# OpenTallas memory compiler (tools/mem_compiler), ASAP7 abstract view
VERSION 5.7 ;
BUSBITCHARS "[]" ;
DIVIDERCHAR "/" ;
PROPERTYDEFINITIONS
  MACRO width INTEGER ;
  MACRO depth INTEGER ;
  MACRO banks INTEGER ;
END PROPERTYDEFINITIONS
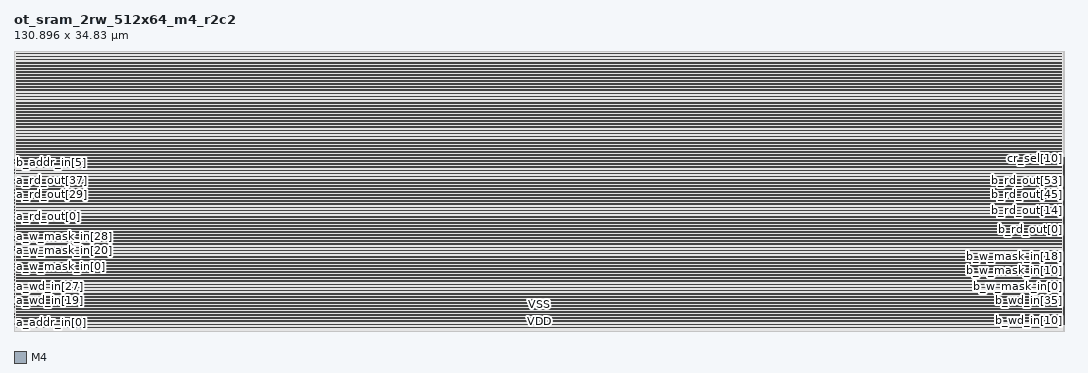
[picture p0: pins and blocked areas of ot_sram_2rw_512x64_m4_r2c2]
MACRO ot_sram_2rw_512x64_m4_r2c2
  PROPERTY width 64 ;
  PROPERTY depth 512 ;
  PROPERTY banks 1 ;
  FOREIGN ot_sram_2rw_512x64_m4_r2c2 0 0 ;
  SYMMETRY X Y R90 ;
  SIZE 130.896 BY 34.830 ;
  CLASS BLOCK ;
  PIN clk
    DIRECTION INPUT ;
    USE CLOCK ;
    SHAPE ABUTMENT ;
    PORT
      LAYER M4 ;
      RECT 0.000 0.768 0.024 0.792 ;
    END
  END clk
  PIN a_ce_in
    DIRECTION INPUT ;
    USE SIGNAL ;
    SHAPE ABUTMENT ;
    PORT
      LAYER M4 ;
      RECT 0.000 0.864 0.024 0.888 ;
    END
  END a_ce_in
  PIN a_we_in
    DIRECTION INPUT ;
    USE SIGNAL ;
    SHAPE ABUTMENT ;
    PORT
      LAYER M4 ;
      RECT 0.000 0.960 0.024 0.984 ;
    END
  END a_we_in
  PIN a_addr_in[0]
    DIRECTION INPUT ;
    USE SIGNAL ;
    SHAPE ABUTMENT ;
    PORT
      LAYER M4 ;
      RECT 0.000 1.056 0.024 1.080 ;
    END
  END a_addr_in[0]
  PIN a_addr_in[1]
    DIRECTION INPUT ;
    USE SIGNAL ;
    SHAPE ABUTMENT ;
    PORT
      LAYER M4 ;
      RECT 0.000 1.152 0.024 1.176 ;
    END
  END a_addr_in[1]
  PIN a_addr_in[2]
    DIRECTION INPUT ;
    USE SIGNAL ;
    SHAPE ABUTMENT ;
    PORT
      LAYER M4 ;
      RECT 0.000 1.248 0.024 1.272 ;
    END
  END a_addr_in[2]
  PIN a_addr_in[3]
    DIRECTION INPUT ;
    USE SIGNAL ;
    SHAPE ABUTMENT ;
    PORT
      LAYER M4 ;
      RECT 0.000 1.344 0.024 1.368 ;
    END
  END a_addr_in[3]
  PIN a_addr_in[4]
    DIRECTION INPUT ;
    USE SIGNAL ;
    SHAPE ABUTMENT ;
    PORT
      LAYER M4 ;
      RECT 0.000 1.440 0.024 1.464 ;
    END
  END a_addr_in[4]
  PIN a_addr_in[5]
    DIRECTION INPUT ;
    USE SIGNAL ;
    SHAPE ABUTMENT ;
    PORT
      LAYER M4 ;
      RECT 0.000 1.536 0.024 1.560 ;
    END
  END a_addr_in[5]
  PIN a_addr_in[6]
    DIRECTION INPUT ;
    USE SIGNAL ;
    SHAPE ABUTMENT ;
    PORT
      LAYER M4 ;
      RECT 0.000 1.632 0.024 1.656 ;
    END
  END a_addr_in[6]
  PIN a_addr_in[7]
    DIRECTION INPUT ;
    USE SIGNAL ;
    SHAPE ABUTMENT ;
    PORT
      LAYER M4 ;
      RECT 0.000 1.728 0.024 1.752 ;
    END
  END a_addr_in[7]
  PIN a_addr_in[8]
    DIRECTION INPUT ;
    USE SIGNAL ;
    SHAPE ABUTMENT ;
    PORT
      LAYER M4 ;
      RECT 0.000 1.824 0.024 1.848 ;
    END
  END a_addr_in[8]
  PIN a_wd_in[0]
    DIRECTION INPUT ;
    USE SIGNAL ;
    SHAPE ABUTMENT ;
    PORT
      LAYER M4 ;
      RECT 0.000 1.920 0.024 1.944 ;
    END
  END a_wd_in[0]
  PIN a_wd_in[1]
    DIRECTION INPUT ;
    USE SIGNAL ;
    SHAPE ABUTMENT ;
    PORT
      LAYER M4 ;
      RECT 0.000 2.016 0.024 2.040 ;
    END
  END a_wd_in[1]
  PIN a_wd_in[2]
    DIRECTION INPUT ;
    USE SIGNAL ;
    SHAPE ABUTMENT ;
    PORT
      LAYER M4 ;
      RECT 0.000 2.112 0.024 2.136 ;
    END
  END a_wd_in[2]
  PIN a_wd_in[3]
    DIRECTION INPUT ;
    USE SIGNAL ;
    SHAPE ABUTMENT ;
    PORT
      LAYER M4 ;
      RECT 0.000 2.208 0.024 2.232 ;
    END
  END a_wd_in[3]
  PIN a_wd_in[4]
    DIRECTION INPUT ;
    USE SIGNAL ;
    SHAPE ABUTMENT ;
    PORT
      LAYER M4 ;
      RECT 0.000 2.304 0.024 2.328 ;
    END
  END a_wd_in[4]
  PIN a_wd_in[5]
    DIRECTION INPUT ;
    USE SIGNAL ;
    SHAPE ABUTMENT ;
    PORT
      LAYER M4 ;
      RECT 0.000 2.400 0.024 2.424 ;
    END
  END a_wd_in[5]
  PIN a_wd_in[6]
    DIRECTION INPUT ;
    USE SIGNAL ;
    SHAPE ABUTMENT ;
    PORT
      LAYER M4 ;
      RECT 0.000 2.496 0.024 2.520 ;
    END
  END a_wd_in[6]
  PIN a_wd_in[7]
    DIRECTION INPUT ;
    USE SIGNAL ;
    SHAPE ABUTMENT ;
    PORT
      LAYER M4 ;
      RECT 0.000 2.592 0.024 2.616 ;
    END
  END a_wd_in[7]
  PIN a_wd_in[8]
    DIRECTION INPUT ;
    USE SIGNAL ;
    SHAPE ABUTMENT ;
    PORT
      LAYER M4 ;
      RECT 0.000 2.688 0.024 2.712 ;
    END
  END a_wd_in[8]
  PIN a_wd_in[9]
    DIRECTION INPUT ;
    USE SIGNAL ;
    SHAPE ABUTMENT ;
    PORT
      LAYER M4 ;
      RECT 0.000 2.784 0.024 2.808 ;
    END
  END a_wd_in[9]
  PIN a_wd_in[10]
    DIRECTION INPUT ;
    USE SIGNAL ;
    SHAPE ABUTMENT ;
    PORT
      LAYER M4 ;
      RECT 0.000 2.880 0.024 2.904 ;
    END
  END a_wd_in[10]
  PIN a_wd_in[11]
    DIRECTION INPUT ;
    USE SIGNAL ;
    SHAPE ABUTMENT ;
    PORT
      LAYER M4 ;
      RECT 0.000 2.976 0.024 3.000 ;
    END
  END a_wd_in[11]
  PIN a_wd_in[12]
    DIRECTION INPUT ;
    USE SIGNAL ;
    SHAPE ABUTMENT ;
    PORT
      LAYER M4 ;
      RECT 0.000 3.072 0.024 3.096 ;
    END
  END a_wd_in[12]
  PIN a_wd_in[13]
    DIRECTION INPUT ;
    USE SIGNAL ;
    SHAPE ABUTMENT ;
    PORT
      LAYER M4 ;
      RECT 0.000 3.168 0.024 3.192 ;
    END
  END a_wd_in[13]
  PIN a_wd_in[14]
    DIRECTION INPUT ;
    USE SIGNAL ;
    SHAPE ABUTMENT ;
    PORT
      LAYER M4 ;
      RECT 0.000 3.264 0.024 3.288 ;
    END
  END a_wd_in[14]
  PIN a_wd_in[15]
    DIRECTION INPUT ;
    USE SIGNAL ;
    SHAPE ABUTMENT ;
    PORT
      LAYER M4 ;
      RECT 0.000 3.360 0.024 3.384 ;
    END
  END a_wd_in[15]
  PIN a_wd_in[16]
    DIRECTION INPUT ;
    USE SIGNAL ;
    SHAPE ABUTMENT ;
    PORT
      LAYER M4 ;
      RECT 0.000 3.456 0.024 3.480 ;
    END
  END a_wd_in[16]
  PIN a_wd_in[17]
    DIRECTION INPUT ;
    USE SIGNAL ;
    SHAPE ABUTMENT ;
    PORT
      LAYER M4 ;
      RECT 0.000 3.552 0.024 3.576 ;
    END
  END a_wd_in[17]
  PIN a_wd_in[18]
    DIRECTION INPUT ;
    USE SIGNAL ;
    SHAPE ABUTMENT ;
    PORT
      LAYER M4 ;
      RECT 0.000 3.648 0.024 3.672 ;
    END
  END a_wd_in[18]
  PIN a_wd_in[19]
    DIRECTION INPUT ;
    USE SIGNAL ;
    SHAPE ABUTMENT ;
    PORT
      LAYER M4 ;
      RECT 0.000 3.744 0.024 3.768 ;
    END
  END a_wd_in[19]
  PIN a_wd_in[20]
    DIRECTION INPUT ;
    USE SIGNAL ;
    SHAPE ABUTMENT ;
    PORT
      LAYER M4 ;
      RECT 0.000 3.840 0.024 3.864 ;
    END
  END a_wd_in[20]
  PIN a_wd_in[21]
    DIRECTION INPUT ;
    USE SIGNAL ;
    SHAPE ABUTMENT ;
    PORT
      LAYER M4 ;
      RECT 0.000 3.936 0.024 3.960 ;
    END
  END a_wd_in[21]
  PIN a_wd_in[22]
    DIRECTION INPUT ;
    USE SIGNAL ;
    SHAPE ABUTMENT ;
    PORT
      LAYER M4 ;
      RECT 0.000 4.032 0.024 4.056 ;
    END
  END a_wd_in[22]
  PIN a_wd_in[23]
    DIRECTION INPUT ;
    USE SIGNAL ;
    SHAPE ABUTMENT ;
    PORT
      LAYER M4 ;
      RECT 0.000 4.128 0.024 4.152 ;
    END
  END a_wd_in[23]
  PIN a_wd_in[24]
    DIRECTION INPUT ;
    USE SIGNAL ;
    SHAPE ABUTMENT ;
    PORT
      LAYER M4 ;
      RECT 0.000 4.224 0.024 4.248 ;
    END
  END a_wd_in[24]
  PIN a_wd_in[25]
    DIRECTION INPUT ;
    USE SIGNAL ;
    SHAPE ABUTMENT ;
    PORT
      LAYER M4 ;
      RECT 0.000 4.320 0.024 4.344 ;
    END
  END a_wd_in[25]
  PIN a_wd_in[26]
    DIRECTION INPUT ;
    USE SIGNAL ;
    SHAPE ABUTMENT ;
    PORT
      LAYER M4 ;
      RECT 0.000 4.416 0.024 4.440 ;
    END
  END a_wd_in[26]
  PIN a_wd_in[27]
    DIRECTION INPUT ;
    USE SIGNAL ;
    SHAPE ABUTMENT ;
    PORT
      LAYER M4 ;
      RECT 0.000 4.512 0.024 4.536 ;
    END
  END a_wd_in[27]
  PIN a_wd_in[28]
    DIRECTION INPUT ;
    USE SIGNAL ;
    SHAPE ABUTMENT ;
    PORT
      LAYER M4 ;
      RECT 0.000 4.608 0.024 4.632 ;
    END
  END a_wd_in[28]
  PIN a_wd_in[29]
    DIRECTION INPUT ;
    USE SIGNAL ;
    SHAPE ABUTMENT ;
    PORT
      LAYER M4 ;
      RECT 0.000 4.704 0.024 4.728 ;
    END
  END a_wd_in[29]
  PIN a_wd_in[30]
    DIRECTION INPUT ;
    USE SIGNAL ;
    SHAPE ABUTMENT ;
    PORT
      LAYER M4 ;
      RECT 0.000 4.800 0.024 4.824 ;
    END
  END a_wd_in[30]
  PIN a_wd_in[31]
    DIRECTION INPUT ;
    USE SIGNAL ;
    SHAPE ABUTMENT ;
    PORT
      LAYER M4 ;
      RECT 0.000 4.896 0.024 4.920 ;
    END
  END a_wd_in[31]
  PIN a_wd_in[32]
    DIRECTION INPUT ;
    USE SIGNAL ;
    SHAPE ABUTMENT ;
    PORT
      LAYER M4 ;
      RECT 0.000 4.992 0.024 5.016 ;
    END
  END a_wd_in[32]
  PIN a_wd_in[33]
    DIRECTION INPUT ;
    USE SIGNAL ;
    SHAPE ABUTMENT ;
    PORT
      LAYER M4 ;
      RECT 0.000 5.088 0.024 5.112 ;
    END
  END a_wd_in[33]
  PIN a_wd_in[34]
    DIRECTION INPUT ;
    USE SIGNAL ;
    SHAPE ABUTMENT ;
    PORT
      LAYER M4 ;
      RECT 0.000 5.184 0.024 5.208 ;
    END
  END a_wd_in[34]
  PIN a_wd_in[35]
    DIRECTION INPUT ;
    USE SIGNAL ;
    SHAPE ABUTMENT ;
    PORT
      LAYER M4 ;
      RECT 0.000 5.280 0.024 5.304 ;
    END
  END a_wd_in[35]
  PIN a_wd_in[36]
    DIRECTION INPUT ;
    USE SIGNAL ;
    SHAPE ABUTMENT ;
    PORT
      LAYER M4 ;
      RECT 0.000 5.376 0.024 5.400 ;
    END
  END a_wd_in[36]
  PIN a_wd_in[37]
    DIRECTION INPUT ;
    USE SIGNAL ;
    SHAPE ABUTMENT ;
    PORT
      LAYER M4 ;
      RECT 0.000 5.472 0.024 5.496 ;
    END
  END a_wd_in[37]
  PIN a_wd_in[38]
    DIRECTION INPUT ;
    USE SIGNAL ;
    SHAPE ABUTMENT ;
    PORT
      LAYER M4 ;
      RECT 0.000 5.568 0.024 5.592 ;
    END
  END a_wd_in[38]
  PIN a_wd_in[39]
    DIRECTION INPUT ;
    USE SIGNAL ;
    SHAPE ABUTMENT ;
    PORT
      LAYER M4 ;
      RECT 0.000 5.664 0.024 5.688 ;
    END
  END a_wd_in[39]
  PIN a_wd_in[40]
    DIRECTION INPUT ;
    USE SIGNAL ;
    SHAPE ABUTMENT ;
    PORT
      LAYER M4 ;
      RECT 0.000 5.760 0.024 5.784 ;
    END
  END a_wd_in[40]
  PIN a_wd_in[41]
    DIRECTION INPUT ;
    USE SIGNAL ;
    SHAPE ABUTMENT ;
    PORT
      LAYER M4 ;
      RECT 0.000 5.856 0.024 5.880 ;
    END
  END a_wd_in[41]
  PIN a_wd_in[42]
    DIRECTION INPUT ;
    USE SIGNAL ;
    SHAPE ABUTMENT ;
    PORT
      LAYER M4 ;
      RECT 0.000 5.952 0.024 5.976 ;
    END
  END a_wd_in[42]
  PIN a_wd_in[43]
    DIRECTION INPUT ;
    USE SIGNAL ;
    SHAPE ABUTMENT ;
    PORT
      LAYER M4 ;
      RECT 0.000 6.048 0.024 6.072 ;
    END
  END a_wd_in[43]
  PIN a_wd_in[44]
    DIRECTION INPUT ;
    USE SIGNAL ;
    SHAPE ABUTMENT ;
    PORT
      LAYER M4 ;
      RECT 0.000 6.144 0.024 6.168 ;
    END
  END a_wd_in[44]
  PIN a_wd_in[45]
    DIRECTION INPUT ;
    USE SIGNAL ;
    SHAPE ABUTMENT ;
    PORT
      LAYER M4 ;
      RECT 0.000 6.240 0.024 6.264 ;
    END
  END a_wd_in[45]
  PIN a_wd_in[46]
    DIRECTION INPUT ;
    USE SIGNAL ;
    SHAPE ABUTMENT ;
    PORT
      LAYER M4 ;
      RECT 0.000 6.336 0.024 6.360 ;
    END
  END a_wd_in[46]
  PIN a_wd_in[47]
    DIRECTION INPUT ;
    USE SIGNAL ;
    SHAPE ABUTMENT ;
    PORT
      LAYER M4 ;
      RECT 0.000 6.432 0.024 6.456 ;
    END
  END a_wd_in[47]
  PIN a_wd_in[48]
    DIRECTION INPUT ;
    USE SIGNAL ;
    SHAPE ABUTMENT ;
    PORT
      LAYER M4 ;
      RECT 0.000 6.528 0.024 6.552 ;
    END
  END a_wd_in[48]
  PIN a_wd_in[49]
    DIRECTION INPUT ;
    USE SIGNAL ;
    SHAPE ABUTMENT ;
    PORT
      LAYER M4 ;
      RECT 0.000 6.624 0.024 6.648 ;
    END
  END a_wd_in[49]
  PIN a_wd_in[50]
    DIRECTION INPUT ;
    USE SIGNAL ;
    SHAPE ABUTMENT ;
    PORT
      LAYER M4 ;
      RECT 0.000 6.720 0.024 6.744 ;
    END
  END a_wd_in[50]
  PIN a_wd_in[51]
    DIRECTION INPUT ;
    USE SIGNAL ;
    SHAPE ABUTMENT ;
    PORT
      LAYER M4 ;
      RECT 0.000 6.816 0.024 6.840 ;
    END
  END a_wd_in[51]
  PIN a_wd_in[52]
    DIRECTION INPUT ;
    USE SIGNAL ;
    SHAPE ABUTMENT ;
    PORT
      LAYER M4 ;
      RECT 0.000 6.912 0.024 6.936 ;
    END
  END a_wd_in[52]
  PIN a_wd_in[53]
    DIRECTION INPUT ;
    USE SIGNAL ;
    SHAPE ABUTMENT ;
    PORT
      LAYER M4 ;
      RECT 0.000 7.008 0.024 7.032 ;
    END
  END a_wd_in[53]
  PIN a_wd_in[54]
    DIRECTION INPUT ;
    USE SIGNAL ;
    SHAPE ABUTMENT ;
    PORT
      LAYER M4 ;
      RECT 0.000 7.104 0.024 7.128 ;
    END
  END a_wd_in[54]
  PIN a_wd_in[55]
    DIRECTION INPUT ;
    USE SIGNAL ;
    SHAPE ABUTMENT ;
    PORT
      LAYER M4 ;
      RECT 0.000 7.200 0.024 7.224 ;
    END
  END a_wd_in[55]
  PIN a_wd_in[56]
    DIRECTION INPUT ;
    USE SIGNAL ;
    SHAPE ABUTMENT ;
    PORT
      LAYER M4 ;
      RECT 0.000 7.296 0.024 7.320 ;
    END
  END a_wd_in[56]
  PIN a_wd_in[57]
    DIRECTION INPUT ;
    USE SIGNAL ;
    SHAPE ABUTMENT ;
    PORT
      LAYER M4 ;
      RECT 0.000 7.392 0.024 7.416 ;
    END
  END a_wd_in[57]
  PIN a_wd_in[58]
    DIRECTION INPUT ;
    USE SIGNAL ;
    SHAPE ABUTMENT ;
    PORT
      LAYER M4 ;
      RECT 0.000 7.488 0.024 7.512 ;
    END
  END a_wd_in[58]
  PIN a_wd_in[59]
    DIRECTION INPUT ;
    USE SIGNAL ;
    SHAPE ABUTMENT ;
    PORT
      LAYER M4 ;
      RECT 0.000 7.584 0.024 7.608 ;
    END
  END a_wd_in[59]
  PIN a_wd_in[60]
    DIRECTION INPUT ;
    USE SIGNAL ;
    SHAPE ABUTMENT ;
    PORT
      LAYER M4 ;
      RECT 0.000 7.680 0.024 7.704 ;
    END
  END a_wd_in[60]
  PIN a_wd_in[61]
    DIRECTION INPUT ;
    USE SIGNAL ;
    SHAPE ABUTMENT ;
    PORT
      LAYER M4 ;
      RECT 0.000 7.776 0.024 7.800 ;
    END
  END a_wd_in[61]
  PIN a_wd_in[62]
    DIRECTION INPUT ;
    USE SIGNAL ;
    SHAPE ABUTMENT ;
    PORT
      LAYER M4 ;
      RECT 0.000 7.872 0.024 7.896 ;
    END
  END a_wd_in[62]
  PIN a_wd_in[63]
    DIRECTION INPUT ;
    USE SIGNAL ;
    SHAPE ABUTMENT ;
    PORT
      LAYER M4 ;
      RECT 0.000 7.968 0.024 7.992 ;
    END
  END a_wd_in[63]
  PIN a_w_mask_in[0]
    DIRECTION INPUT ;
    USE SIGNAL ;
    SHAPE ABUTMENT ;
    PORT
      LAYER M4 ;
      RECT 0.000 8.064 0.024 8.088 ;
    END
  END a_w_mask_in[0]
  PIN a_w_mask_in[1]
    DIRECTION INPUT ;
    USE SIGNAL ;
    SHAPE ABUTMENT ;
    PORT
      LAYER M4 ;
      RECT 0.000 8.160 0.024 8.184 ;
    END
  END a_w_mask_in[1]
  PIN a_w_mask_in[2]
    DIRECTION INPUT ;
    USE SIGNAL ;
    SHAPE ABUTMENT ;
    PORT
      LAYER M4 ;
      RECT 0.000 8.256 0.024 8.280 ;
    END
  END a_w_mask_in[2]
  PIN a_w_mask_in[3]
    DIRECTION INPUT ;
    USE SIGNAL ;
    SHAPE ABUTMENT ;
    PORT
      LAYER M4 ;
      RECT 0.000 8.352 0.024 8.376 ;
    END
  END a_w_mask_in[3]
  PIN a_w_mask_in[4]
    DIRECTION INPUT ;
    USE SIGNAL ;
    SHAPE ABUTMENT ;
    PORT
      LAYER M4 ;
      RECT 0.000 8.448 0.024 8.472 ;
    END
  END a_w_mask_in[4]
  PIN a_w_mask_in[5]
    DIRECTION INPUT ;
    USE SIGNAL ;
    SHAPE ABUTMENT ;
    PORT
      LAYER M4 ;
      RECT 0.000 8.544 0.024 8.568 ;
    END
  END a_w_mask_in[5]
  PIN a_w_mask_in[6]
    DIRECTION INPUT ;
    USE SIGNAL ;
    SHAPE ABUTMENT ;
    PORT
      LAYER M4 ;
      RECT 0.000 8.640 0.024 8.664 ;
    END
  END a_w_mask_in[6]
  PIN a_w_mask_in[7]
    DIRECTION INPUT ;
    USE SIGNAL ;
    SHAPE ABUTMENT ;
    PORT
      LAYER M4 ;
      RECT 0.000 8.736 0.024 8.760 ;
    END
  END a_w_mask_in[7]
  PIN a_w_mask_in[8]
    DIRECTION INPUT ;
    USE SIGNAL ;
    SHAPE ABUTMENT ;
    PORT
      LAYER M4 ;
      RECT 0.000 8.832 0.024 8.856 ;
    END
  END a_w_mask_in[8]
  PIN a_w_mask_in[9]
    DIRECTION INPUT ;
    USE SIGNAL ;
    SHAPE ABUTMENT ;
    PORT
      LAYER M4 ;
      RECT 0.000 8.928 0.024 8.952 ;
    END
  END a_w_mask_in[9]
  PIN a_w_mask_in[10]
    DIRECTION INPUT ;
    USE SIGNAL ;
    SHAPE ABUTMENT ;
    PORT
      LAYER M4 ;
      RECT 0.000 9.024 0.024 9.048 ;
    END
  END a_w_mask_in[10]
  PIN a_w_mask_in[11]
    DIRECTION INPUT ;
    USE SIGNAL ;
    SHAPE ABUTMENT ;
    PORT
      LAYER M4 ;
      RECT 0.000 9.120 0.024 9.144 ;
    END
  END a_w_mask_in[11]
  PIN a_w_mask_in[12]
    DIRECTION INPUT ;
    USE SIGNAL ;
    SHAPE ABUTMENT ;
    PORT
      LAYER M4 ;
      RECT 0.000 9.216 0.024 9.240 ;
    END
  END a_w_mask_in[12]
  PIN a_w_mask_in[13]
    DIRECTION INPUT ;
    USE SIGNAL ;
    SHAPE ABUTMENT ;
    PORT
      LAYER M4 ;
      RECT 0.000 9.312 0.024 9.336 ;
    END
  END a_w_mask_in[13]
  PIN a_w_mask_in[14]
    DIRECTION INPUT ;
    USE SIGNAL ;
    SHAPE ABUTMENT ;
    PORT
      LAYER M4 ;
      RECT 0.000 9.408 0.024 9.432 ;
    END
  END a_w_mask_in[14]
  PIN a_w_mask_in[15]
    DIRECTION INPUT ;
    USE SIGNAL ;
    SHAPE ABUTMENT ;
    PORT
      LAYER M4 ;
      RECT 0.000 9.504 0.024 9.528 ;
    END
  END a_w_mask_in[15]
  PIN a_w_mask_in[16]
    DIRECTION INPUT ;
    USE SIGNAL ;
    SHAPE ABUTMENT ;
    PORT
      LAYER M4 ;
      RECT 0.000 9.600 0.024 9.624 ;
    END
  END a_w_mask_in[16]
  PIN a_w_mask_in[17]
    DIRECTION INPUT ;
    USE SIGNAL ;
    SHAPE ABUTMENT ;
    PORT
      LAYER M4 ;
      RECT 0.000 9.696 0.024 9.720 ;
    END
  END a_w_mask_in[17]
  PIN a_w_mask_in[18]
    DIRECTION INPUT ;
    USE SIGNAL ;
    SHAPE ABUTMENT ;
    PORT
      LAYER M4 ;
      RECT 0.000 9.792 0.024 9.816 ;
    END
  END a_w_mask_in[18]
  PIN a_w_mask_in[19]
    DIRECTION INPUT ;
    USE SIGNAL ;
    SHAPE ABUTMENT ;
    PORT
      LAYER M4 ;
      RECT 0.000 9.888 0.024 9.912 ;
    END
  END a_w_mask_in[19]
  PIN a_w_mask_in[20]
    DIRECTION INPUT ;
    USE SIGNAL ;
    SHAPE ABUTMENT ;
    PORT
      LAYER M4 ;
      RECT 0.000 9.984 0.024 10.008 ;
    END
  END a_w_mask_in[20]
  PIN a_w_mask_in[21]
    DIRECTION INPUT ;
    USE SIGNAL ;
    SHAPE ABUTMENT ;
    PORT
      LAYER M4 ;
      RECT 0.000 10.080 0.024 10.104 ;
    END
  END a_w_mask_in[21]
  PIN a_w_mask_in[22]
    DIRECTION INPUT ;
    USE SIGNAL ;
    SHAPE ABUTMENT ;
    PORT
      LAYER M4 ;
      RECT 0.000 10.176 0.024 10.200 ;
    END
  END a_w_mask_in[22]
  PIN a_w_mask_in[23]
    DIRECTION INPUT ;
    USE SIGNAL ;
    SHAPE ABUTMENT ;
    PORT
      LAYER M4 ;
      RECT 0.000 10.272 0.024 10.296 ;
    END
  END a_w_mask_in[23]
  PIN a_w_mask_in[24]
    DIRECTION INPUT ;
    USE SIGNAL ;
    SHAPE ABUTMENT ;
    PORT
      LAYER M4 ;
      RECT 0.000 10.368 0.024 10.392 ;
    END
  END a_w_mask_in[24]
  PIN a_w_mask_in[25]
    DIRECTION INPUT ;
    USE SIGNAL ;
    SHAPE ABUTMENT ;
    PORT
      LAYER M4 ;
      RECT 0.000 10.464 0.024 10.488 ;
    END
  END a_w_mask_in[25]
  PIN a_w_mask_in[26]
    DIRECTION INPUT ;
    USE SIGNAL ;
    SHAPE ABUTMENT ;
    PORT
      LAYER M4 ;
      RECT 0.000 10.560 0.024 10.584 ;
    END
  END a_w_mask_in[26]
  PIN a_w_mask_in[27]
    DIRECTION INPUT ;
    USE SIGNAL ;
    SHAPE ABUTMENT ;
    PORT
      LAYER M4 ;
      RECT 0.000 10.656 0.024 10.680 ;
    END
  END a_w_mask_in[27]
  PIN a_w_mask_in[28]
    DIRECTION INPUT ;
    USE SIGNAL ;
    SHAPE ABUTMENT ;
    PORT
      LAYER M4 ;
      RECT 0.000 10.752 0.024 10.776 ;
    END
  END a_w_mask_in[28]
  PIN a_w_mask_in[29]
    DIRECTION INPUT ;
    USE SIGNAL ;
    SHAPE ABUTMENT ;
    PORT
      LAYER M4 ;
      RECT 0.000 10.848 0.024 10.872 ;
    END
  END a_w_mask_in[29]
  PIN a_w_mask_in[30]
    DIRECTION INPUT ;
    USE SIGNAL ;
    SHAPE ABUTMENT ;
    PORT
      LAYER M4 ;
      RECT 0.000 10.944 0.024 10.968 ;
    END
  END a_w_mask_in[30]
  PIN a_w_mask_in[31]
    DIRECTION INPUT ;
    USE SIGNAL ;
    SHAPE ABUTMENT ;
    PORT
      LAYER M4 ;
      RECT 0.000 11.040 0.024 11.064 ;
    END
  END a_w_mask_in[31]
  PIN a_w_mask_in[32]
    DIRECTION INPUT ;
    USE SIGNAL ;
    SHAPE ABUTMENT ;
    PORT
      LAYER M4 ;
      RECT 0.000 11.136 0.024 11.160 ;
    END
  END a_w_mask_in[32]
  PIN a_w_mask_in[33]
    DIRECTION INPUT ;
    USE SIGNAL ;
    SHAPE ABUTMENT ;
    PORT
      LAYER M4 ;
      RECT 0.000 11.232 0.024 11.256 ;
    END
  END a_w_mask_in[33]
  PIN a_w_mask_in[34]
    DIRECTION INPUT ;
    USE SIGNAL ;
    SHAPE ABUTMENT ;
    PORT
      LAYER M4 ;
      RECT 0.000 11.328 0.024 11.352 ;
    END
  END a_w_mask_in[34]
  PIN a_w_mask_in[35]
    DIRECTION INPUT ;
    USE SIGNAL ;
    SHAPE ABUTMENT ;
    PORT
      LAYER M4 ;
      RECT 0.000 11.424 0.024 11.448 ;
    END
  END a_w_mask_in[35]
  PIN a_w_mask_in[36]
    DIRECTION INPUT ;
    USE SIGNAL ;
    SHAPE ABUTMENT ;
    PORT
      LAYER M4 ;
      RECT 0.000 11.520 0.024 11.544 ;
    END
  END a_w_mask_in[36]
  PIN a_w_mask_in[37]
    DIRECTION INPUT ;
    USE SIGNAL ;
    SHAPE ABUTMENT ;
    PORT
      LAYER M4 ;
      RECT 0.000 11.616 0.024 11.640 ;
    END
  END a_w_mask_in[37]
  PIN a_w_mask_in[38]
    DIRECTION INPUT ;
    USE SIGNAL ;
    SHAPE ABUTMENT ;
    PORT
      LAYER M4 ;
      RECT 0.000 11.712 0.024 11.736 ;
    END
  END a_w_mask_in[38]
  PIN a_w_mask_in[39]
    DIRECTION INPUT ;
    USE SIGNAL ;
    SHAPE ABUTMENT ;
    PORT
      LAYER M4 ;
      RECT 0.000 11.808 0.024 11.832 ;
    END
  END a_w_mask_in[39]
  PIN a_w_mask_in[40]
    DIRECTION INPUT ;
    USE SIGNAL ;
    SHAPE ABUTMENT ;
    PORT
      LAYER M4 ;
      RECT 0.000 11.904 0.024 11.928 ;
    END
  END a_w_mask_in[40]
  PIN a_w_mask_in[41]
    DIRECTION INPUT ;
    USE SIGNAL ;
    SHAPE ABUTMENT ;
    PORT
      LAYER M4 ;
      RECT 0.000 12.000 0.024 12.024 ;
    END
  END a_w_mask_in[41]
  PIN a_w_mask_in[42]
    DIRECTION INPUT ;
    USE SIGNAL ;
    SHAPE ABUTMENT ;
    PORT
      LAYER M4 ;
      RECT 0.000 12.096 0.024 12.120 ;
    END
  END a_w_mask_in[42]
  PIN a_w_mask_in[43]
    DIRECTION INPUT ;
    USE SIGNAL ;
    SHAPE ABUTMENT ;
    PORT
      LAYER M4 ;
      RECT 0.000 12.192 0.024 12.216 ;
    END
  END a_w_mask_in[43]
  PIN a_w_mask_in[44]
    DIRECTION INPUT ;
    USE SIGNAL ;
    SHAPE ABUTMENT ;
    PORT
      LAYER M4 ;
      RECT 0.000 12.288 0.024 12.312 ;
    END
  END a_w_mask_in[44]
  PIN a_w_mask_in[45]
    DIRECTION INPUT ;
    USE SIGNAL ;
    SHAPE ABUTMENT ;
    PORT
      LAYER M4 ;
      RECT 0.000 12.384 0.024 12.408 ;
    END
  END a_w_mask_in[45]
  PIN a_w_mask_in[46]
    DIRECTION INPUT ;
    USE SIGNAL ;
    SHAPE ABUTMENT ;
    PORT
      LAYER M4 ;
      RECT 0.000 12.480 0.024 12.504 ;
    END
  END a_w_mask_in[46]
  PIN a_w_mask_in[47]
    DIRECTION INPUT ;
    USE SIGNAL ;
    SHAPE ABUTMENT ;
    PORT
      LAYER M4 ;
      RECT 0.000 12.576 0.024 12.600 ;
    END
  END a_w_mask_in[47]
  PIN a_w_mask_in[48]
    DIRECTION INPUT ;
    USE SIGNAL ;
    SHAPE ABUTMENT ;
    PORT
      LAYER M4 ;
      RECT 0.000 12.672 0.024 12.696 ;
    END
  END a_w_mask_in[48]
  PIN a_w_mask_in[49]
    DIRECTION INPUT ;
    USE SIGNAL ;
    SHAPE ABUTMENT ;
    PORT
      LAYER M4 ;
      RECT 0.000 12.768 0.024 12.792 ;
    END
  END a_w_mask_in[49]
  PIN a_w_mask_in[50]
    DIRECTION INPUT ;
    USE SIGNAL ;
    SHAPE ABUTMENT ;
    PORT
      LAYER M4 ;
      RECT 0.000 12.864 0.024 12.888 ;
    END
  END a_w_mask_in[50]
  PIN a_w_mask_in[51]
    DIRECTION INPUT ;
    USE SIGNAL ;
    SHAPE ABUTMENT ;
    PORT
      LAYER M4 ;
      RECT 0.000 12.960 0.024 12.984 ;
    END
  END a_w_mask_in[51]
  PIN a_w_mask_in[52]
    DIRECTION INPUT ;
    USE SIGNAL ;
    SHAPE ABUTMENT ;
    PORT
      LAYER M4 ;
      RECT 0.000 13.056 0.024 13.080 ;
    END
  END a_w_mask_in[52]
  PIN a_w_mask_in[53]
    DIRECTION INPUT ;
    USE SIGNAL ;
    SHAPE ABUTMENT ;
    PORT
      LAYER M4 ;
      RECT 0.000 13.152 0.024 13.176 ;
    END
  END a_w_mask_in[53]
  PIN a_w_mask_in[54]
    DIRECTION INPUT ;
    USE SIGNAL ;
    SHAPE ABUTMENT ;
    PORT
      LAYER M4 ;
      RECT 0.000 13.248 0.024 13.272 ;
    END
  END a_w_mask_in[54]
  PIN a_w_mask_in[55]
    DIRECTION INPUT ;
    USE SIGNAL ;
    SHAPE ABUTMENT ;
    PORT
      LAYER M4 ;
      RECT 0.000 13.344 0.024 13.368 ;
    END
  END a_w_mask_in[55]
  PIN a_w_mask_in[56]
    DIRECTION INPUT ;
    USE SIGNAL ;
    SHAPE ABUTMENT ;
    PORT
      LAYER M4 ;
      RECT 0.000 13.440 0.024 13.464 ;
    END
  END a_w_mask_in[56]
  PIN a_w_mask_in[57]
    DIRECTION INPUT ;
    USE SIGNAL ;
    SHAPE ABUTMENT ;
    PORT
      LAYER M4 ;
      RECT 0.000 13.536 0.024 13.560 ;
    END
  END a_w_mask_in[57]
  PIN a_w_mask_in[58]
    DIRECTION INPUT ;
    USE SIGNAL ;
    SHAPE ABUTMENT ;
    PORT
      LAYER M4 ;
      RECT 0.000 13.632 0.024 13.656 ;
    END
  END a_w_mask_in[58]
  PIN a_w_mask_in[59]
    DIRECTION INPUT ;
    USE SIGNAL ;
    SHAPE ABUTMENT ;
    PORT
      LAYER M4 ;
      RECT 0.000 13.728 0.024 13.752 ;
    END
  END a_w_mask_in[59]
  PIN a_w_mask_in[60]
    DIRECTION INPUT ;
    USE SIGNAL ;
    SHAPE ABUTMENT ;
    PORT
      LAYER M4 ;
      RECT 0.000 13.824 0.024 13.848 ;
    END
  END a_w_mask_in[60]
  PIN a_w_mask_in[61]
    DIRECTION INPUT ;
    USE SIGNAL ;
    SHAPE ABUTMENT ;
    PORT
      LAYER M4 ;
      RECT 0.000 13.920 0.024 13.944 ;
    END
  END a_w_mask_in[61]
  PIN a_w_mask_in[62]
    DIRECTION INPUT ;
    USE SIGNAL ;
    SHAPE ABUTMENT ;
    PORT
      LAYER M4 ;
      RECT 0.000 14.016 0.024 14.040 ;
    END
  END a_w_mask_in[62]
  PIN a_w_mask_in[63]
    DIRECTION INPUT ;
    USE SIGNAL ;
    SHAPE ABUTMENT ;
    PORT
      LAYER M4 ;
      RECT 0.000 14.112 0.024 14.136 ;
    END
  END a_w_mask_in[63]
  PIN a_rd_out[0]
    DIRECTION OUTPUT ;
    USE SIGNAL ;
    SHAPE ABUTMENT ;
    PORT
      LAYER M4 ;
      RECT 0.000 14.208 0.024 14.232 ;
    END
  END a_rd_out[0]
  PIN a_rd_out[1]
    DIRECTION OUTPUT ;
    USE SIGNAL ;
    SHAPE ABUTMENT ;
    PORT
      LAYER M4 ;
      RECT 0.000 14.304 0.024 14.328 ;
    END
  END a_rd_out[1]
  PIN a_rd_out[2]
    DIRECTION OUTPUT ;
    USE SIGNAL ;
    SHAPE ABUTMENT ;
    PORT
      LAYER M4 ;
      RECT 0.000 14.400 0.024 14.424 ;
    END
  END a_rd_out[2]
  PIN a_rd_out[3]
    DIRECTION OUTPUT ;
    USE SIGNAL ;
    SHAPE ABUTMENT ;
    PORT
      LAYER M4 ;
      RECT 0.000 14.496 0.024 14.520 ;
    END
  END a_rd_out[3]
  PIN a_rd_out[4]
    DIRECTION OUTPUT ;
    USE SIGNAL ;
    SHAPE ABUTMENT ;
    PORT
      LAYER M4 ;
      RECT 0.000 14.592 0.024 14.616 ;
    END
  END a_rd_out[4]
  PIN a_rd_out[5]
    DIRECTION OUTPUT ;
    USE SIGNAL ;
    SHAPE ABUTMENT ;
    PORT
      LAYER M4 ;
      RECT 0.000 14.688 0.024 14.712 ;
    END
  END a_rd_out[5]
  PIN a_rd_out[6]
    DIRECTION OUTPUT ;
    USE SIGNAL ;
    SHAPE ABUTMENT ;
    PORT
      LAYER M4 ;
      RECT 0.000 14.784 0.024 14.808 ;
    END
  END a_rd_out[6]
  PIN a_rd_out[7]
    DIRECTION OUTPUT ;
    USE SIGNAL ;
    SHAPE ABUTMENT ;
    PORT
      LAYER M4 ;
      RECT 0.000 14.880 0.024 14.904 ;
    END
  END a_rd_out[7]
  PIN a_rd_out[8]
    DIRECTION OUTPUT ;
    USE SIGNAL ;
    SHAPE ABUTMENT ;
    PORT
      LAYER M4 ;
      RECT 0.000 14.976 0.024 15.000 ;
    END
  END a_rd_out[8]
  PIN a_rd_out[9]
    DIRECTION OUTPUT ;
    USE SIGNAL ;
    SHAPE ABUTMENT ;
    PORT
      LAYER M4 ;
      RECT 0.000 15.072 0.024 15.096 ;
    END
  END a_rd_out[9]
  PIN a_rd_out[10]
    DIRECTION OUTPUT ;
    USE SIGNAL ;
    SHAPE ABUTMENT ;
    PORT
      LAYER M4 ;
      RECT 0.000 15.168 0.024 15.192 ;
    END
  END a_rd_out[10]
  PIN a_rd_out[11]
    DIRECTION OUTPUT ;
    USE SIGNAL ;
    SHAPE ABUTMENT ;
    PORT
      LAYER M4 ;
      RECT 0.000 15.264 0.024 15.288 ;
    END
  END a_rd_out[11]
  PIN a_rd_out[12]
    DIRECTION OUTPUT ;
    USE SIGNAL ;
    SHAPE ABUTMENT ;
    PORT
      LAYER M4 ;
      RECT 0.000 15.360 0.024 15.384 ;
    END
  END a_rd_out[12]
  PIN a_rd_out[13]
    DIRECTION OUTPUT ;
    USE SIGNAL ;
    SHAPE ABUTMENT ;
    PORT
      LAYER M4 ;
      RECT 0.000 15.456 0.024 15.480 ;
    END
  END a_rd_out[13]
  PIN a_rd_out[14]
    DIRECTION OUTPUT ;
    USE SIGNAL ;
    SHAPE ABUTMENT ;
    PORT
      LAYER M4 ;
      RECT 0.000 15.552 0.024 15.576 ;
    END
  END a_rd_out[14]
  PIN a_rd_out[15]
    DIRECTION OUTPUT ;
    USE SIGNAL ;
    SHAPE ABUTMENT ;
    PORT
      LAYER M4 ;
      RECT 0.000 15.648 0.024 15.672 ;
    END
  END a_rd_out[15]
  PIN a_rd_out[16]
    DIRECTION OUTPUT ;
    USE SIGNAL ;
    SHAPE ABUTMENT ;
    PORT
      LAYER M4 ;
      RECT 0.000 15.744 0.024 15.768 ;
    END
  END a_rd_out[16]
  PIN a_rd_out[17]
    DIRECTION OUTPUT ;
    USE SIGNAL ;
    SHAPE ABUTMENT ;
    PORT
      LAYER M4 ;
      RECT 0.000 15.840 0.024 15.864 ;
    END
  END a_rd_out[17]
  PIN a_rd_out[18]
    DIRECTION OUTPUT ;
    USE SIGNAL ;
    SHAPE ABUTMENT ;
    PORT
      LAYER M4 ;
      RECT 0.000 15.936 0.024 15.960 ;
    END
  END a_rd_out[18]
  PIN a_rd_out[19]
    DIRECTION OUTPUT ;
    USE SIGNAL ;
    SHAPE ABUTMENT ;
    PORT
      LAYER M4 ;
      RECT 0.000 16.032 0.024 16.056 ;
    END
  END a_rd_out[19]
  PIN a_rd_out[20]
    DIRECTION OUTPUT ;
    USE SIGNAL ;
    SHAPE ABUTMENT ;
    PORT
      LAYER M4 ;
      RECT 0.000 16.128 0.024 16.152 ;
    END
  END a_rd_out[20]
  PIN a_rd_out[21]
    DIRECTION OUTPUT ;
    USE SIGNAL ;
    SHAPE ABUTMENT ;
    PORT
      LAYER M4 ;
      RECT 0.000 16.224 0.024 16.248 ;
    END
  END a_rd_out[21]
  PIN a_rd_out[22]
    DIRECTION OUTPUT ;
    USE SIGNAL ;
    SHAPE ABUTMENT ;
    PORT
      LAYER M4 ;
      RECT 0.000 16.320 0.024 16.344 ;
    END
  END a_rd_out[22]
  PIN a_rd_out[23]
    DIRECTION OUTPUT ;
    USE SIGNAL ;
    SHAPE ABUTMENT ;
    PORT
      LAYER M4 ;
      RECT 0.000 16.416 0.024 16.440 ;
    END
  END a_rd_out[23]
  PIN a_rd_out[24]
    DIRECTION OUTPUT ;
    USE SIGNAL ;
    SHAPE ABUTMENT ;
    PORT
      LAYER M4 ;
      RECT 0.000 16.512 0.024 16.536 ;
    END
  END a_rd_out[24]
  PIN a_rd_out[25]
    DIRECTION OUTPUT ;
    USE SIGNAL ;
    SHAPE ABUTMENT ;
    PORT
      LAYER M4 ;
      RECT 0.000 16.608 0.024 16.632 ;
    END
  END a_rd_out[25]
  PIN a_rd_out[26]
    DIRECTION OUTPUT ;
    USE SIGNAL ;
    SHAPE ABUTMENT ;
    PORT
      LAYER M4 ;
      RECT 0.000 16.704 0.024 16.728 ;
    END
  END a_rd_out[26]
  PIN a_rd_out[27]
    DIRECTION OUTPUT ;
    USE SIGNAL ;
    SHAPE ABUTMENT ;
    PORT
      LAYER M4 ;
      RECT 0.000 16.800 0.024 16.824 ;
    END
  END a_rd_out[27]
  PIN a_rd_out[28]
    DIRECTION OUTPUT ;
    USE SIGNAL ;
    SHAPE ABUTMENT ;
    PORT
      LAYER M4 ;
      RECT 0.000 16.896 0.024 16.920 ;
    END
  END a_rd_out[28]
  PIN a_rd_out[29]
    DIRECTION OUTPUT ;
    USE SIGNAL ;
    SHAPE ABUTMENT ;
    PORT
      LAYER M4 ;
      RECT 0.000 16.992 0.024 17.016 ;
    END
  END a_rd_out[29]
  PIN a_rd_out[30]
    DIRECTION OUTPUT ;
    USE SIGNAL ;
    SHAPE ABUTMENT ;
    PORT
      LAYER M4 ;
      RECT 0.000 17.088 0.024 17.112 ;
    END
  END a_rd_out[30]
  PIN a_rd_out[31]
    DIRECTION OUTPUT ;
    USE SIGNAL ;
    SHAPE ABUTMENT ;
    PORT
      LAYER M4 ;
      RECT 0.000 17.184 0.024 17.208 ;
    END
  END a_rd_out[31]
  PIN a_rd_out[32]
    DIRECTION OUTPUT ;
    USE SIGNAL ;
    SHAPE ABUTMENT ;
    PORT
      LAYER M4 ;
      RECT 0.000 17.280 0.024 17.304 ;
    END
  END a_rd_out[32]
  PIN a_rd_out[33]
    DIRECTION OUTPUT ;
    USE SIGNAL ;
    SHAPE ABUTMENT ;
    PORT
      LAYER M4 ;
      RECT 0.000 17.376 0.024 17.400 ;
    END
  END a_rd_out[33]
  PIN a_rd_out[34]
    DIRECTION OUTPUT ;
    USE SIGNAL ;
    SHAPE ABUTMENT ;
    PORT
      LAYER M4 ;
      RECT 0.000 17.472 0.024 17.496 ;
    END
  END a_rd_out[34]
  PIN a_rd_out[35]
    DIRECTION OUTPUT ;
    USE SIGNAL ;
    SHAPE ABUTMENT ;
    PORT
      LAYER M4 ;
      RECT 0.000 17.568 0.024 17.592 ;
    END
  END a_rd_out[35]
  PIN a_rd_out[36]
    DIRECTION OUTPUT ;
    USE SIGNAL ;
    SHAPE ABUTMENT ;
    PORT
      LAYER M4 ;
      RECT 0.000 17.664 0.024 17.688 ;
    END
  END a_rd_out[36]
  PIN a_rd_out[37]
    DIRECTION OUTPUT ;
    USE SIGNAL ;
    SHAPE ABUTMENT ;
    PORT
      LAYER M4 ;
      RECT 0.000 17.760 0.024 17.784 ;
    END
  END a_rd_out[37]
  PIN a_rd_out[38]
    DIRECTION OUTPUT ;
    USE SIGNAL ;
    SHAPE ABUTMENT ;
    PORT
      LAYER M4 ;
      RECT 0.000 17.856 0.024 17.880 ;
    END
  END a_rd_out[38]
  PIN a_rd_out[39]
    DIRECTION OUTPUT ;
    USE SIGNAL ;
    SHAPE ABUTMENT ;
    PORT
      LAYER M4 ;
      RECT 0.000 17.952 0.024 17.976 ;
    END
  END a_rd_out[39]
  PIN a_rd_out[40]
    DIRECTION OUTPUT ;
    USE SIGNAL ;
    SHAPE ABUTMENT ;
    PORT
      LAYER M4 ;
      RECT 0.000 18.048 0.024 18.072 ;
    END
  END a_rd_out[40]
  PIN a_rd_out[41]
    DIRECTION OUTPUT ;
    USE SIGNAL ;
    SHAPE ABUTMENT ;
    PORT
      LAYER M4 ;
      RECT 0.000 18.144 0.024 18.168 ;
    END
  END a_rd_out[41]
  PIN a_rd_out[42]
    DIRECTION OUTPUT ;
    USE SIGNAL ;
    SHAPE ABUTMENT ;
    PORT
      LAYER M4 ;
      RECT 0.000 18.240 0.024 18.264 ;
    END
  END a_rd_out[42]
  PIN a_rd_out[43]
    DIRECTION OUTPUT ;
    USE SIGNAL ;
    SHAPE ABUTMENT ;
    PORT
      LAYER M4 ;
      RECT 0.000 18.336 0.024 18.360 ;
    END
  END a_rd_out[43]
  PIN a_rd_out[44]
    DIRECTION OUTPUT ;
    USE SIGNAL ;
    SHAPE ABUTMENT ;
    PORT
      LAYER M4 ;
      RECT 0.000 18.432 0.024 18.456 ;
    END
  END a_rd_out[44]
  PIN a_rd_out[45]
    DIRECTION OUTPUT ;
    USE SIGNAL ;
    SHAPE ABUTMENT ;
    PORT
      LAYER M4 ;
      RECT 0.000 18.528 0.024 18.552 ;
    END
  END a_rd_out[45]
  PIN a_rd_out[46]
    DIRECTION OUTPUT ;
    USE SIGNAL ;
    SHAPE ABUTMENT ;
    PORT
      LAYER M4 ;
      RECT 0.000 18.624 0.024 18.648 ;
    END
  END a_rd_out[46]
  PIN a_rd_out[47]
    DIRECTION OUTPUT ;
    USE SIGNAL ;
    SHAPE ABUTMENT ;
    PORT
      LAYER M4 ;
      RECT 0.000 18.720 0.024 18.744 ;
    END
  END a_rd_out[47]
  PIN a_rd_out[48]
    DIRECTION OUTPUT ;
    USE SIGNAL ;
    SHAPE ABUTMENT ;
    PORT
      LAYER M4 ;
      RECT 0.000 18.816 0.024 18.840 ;
    END
  END a_rd_out[48]
  PIN a_rd_out[49]
    DIRECTION OUTPUT ;
    USE SIGNAL ;
    SHAPE ABUTMENT ;
    PORT
      LAYER M4 ;
      RECT 0.000 18.912 0.024 18.936 ;
    END
  END a_rd_out[49]
  PIN a_rd_out[50]
    DIRECTION OUTPUT ;
    USE SIGNAL ;
    SHAPE ABUTMENT ;
    PORT
      LAYER M4 ;
      RECT 0.000 19.008 0.024 19.032 ;
    END
  END a_rd_out[50]
  PIN a_rd_out[51]
    DIRECTION OUTPUT ;
    USE SIGNAL ;
    SHAPE ABUTMENT ;
    PORT
      LAYER M4 ;
      RECT 0.000 19.104 0.024 19.128 ;
    END
  END a_rd_out[51]
  PIN a_rd_out[52]
    DIRECTION OUTPUT ;
    USE SIGNAL ;
    SHAPE ABUTMENT ;
    PORT
      LAYER M4 ;
      RECT 0.000 19.200 0.024 19.224 ;
    END
  END a_rd_out[52]
  PIN a_rd_out[53]
    DIRECTION OUTPUT ;
    USE SIGNAL ;
    SHAPE ABUTMENT ;
    PORT
      LAYER M4 ;
      RECT 0.000 19.296 0.024 19.320 ;
    END
  END a_rd_out[53]
  PIN a_rd_out[54]
    DIRECTION OUTPUT ;
    USE SIGNAL ;
    SHAPE ABUTMENT ;
    PORT
      LAYER M4 ;
      RECT 0.000 19.392 0.024 19.416 ;
    END
  END a_rd_out[54]
  PIN a_rd_out[55]
    DIRECTION OUTPUT ;
    USE SIGNAL ;
    SHAPE ABUTMENT ;
    PORT
      LAYER M4 ;
      RECT 0.000 19.488 0.024 19.512 ;
    END
  END a_rd_out[55]
  PIN a_rd_out[56]
    DIRECTION OUTPUT ;
    USE SIGNAL ;
    SHAPE ABUTMENT ;
    PORT
      LAYER M4 ;
      RECT 0.000 19.584 0.024 19.608 ;
    END
  END a_rd_out[56]
  PIN a_rd_out[57]
    DIRECTION OUTPUT ;
    USE SIGNAL ;
    SHAPE ABUTMENT ;
    PORT
      LAYER M4 ;
      RECT 0.000 19.680 0.024 19.704 ;
    END
  END a_rd_out[57]
  PIN a_rd_out[58]
    DIRECTION OUTPUT ;
    USE SIGNAL ;
    SHAPE ABUTMENT ;
    PORT
      LAYER M4 ;
      RECT 0.000 19.776 0.024 19.800 ;
    END
  END a_rd_out[58]
  PIN a_rd_out[59]
    DIRECTION OUTPUT ;
    USE SIGNAL ;
    SHAPE ABUTMENT ;
    PORT
      LAYER M4 ;
      RECT 0.000 19.872 0.024 19.896 ;
    END
  END a_rd_out[59]
  PIN a_rd_out[60]
    DIRECTION OUTPUT ;
    USE SIGNAL ;
    SHAPE ABUTMENT ;
    PORT
      LAYER M4 ;
      RECT 0.000 19.968 0.024 19.992 ;
    END
  END a_rd_out[60]
  PIN a_rd_out[61]
    DIRECTION OUTPUT ;
    USE SIGNAL ;
    SHAPE ABUTMENT ;
    PORT
      LAYER M4 ;
      RECT 0.000 20.064 0.024 20.088 ;
    END
  END a_rd_out[61]
  PIN a_rd_out[62]
    DIRECTION OUTPUT ;
    USE SIGNAL ;
    SHAPE ABUTMENT ;
    PORT
      LAYER M4 ;
      RECT 0.000 20.160 0.024 20.184 ;
    END
  END a_rd_out[62]
  PIN a_rd_out[63]
    DIRECTION OUTPUT ;
    USE SIGNAL ;
    SHAPE ABUTMENT ;
    PORT
      LAYER M4 ;
      RECT 0.000 20.256 0.024 20.280 ;
    END
  END a_rd_out[63]
  PIN b_ce_in
    DIRECTION INPUT ;
    USE SIGNAL ;
    SHAPE ABUTMENT ;
    PORT
      LAYER M4 ;
      RECT 0.000 20.352 0.024 20.376 ;
    END
  END b_ce_in
  PIN b_we_in
    DIRECTION INPUT ;
    USE SIGNAL ;
    SHAPE ABUTMENT ;
    PORT
      LAYER M4 ;
      RECT 0.000 20.448 0.024 20.472 ;
    END
  END b_we_in
  PIN b_addr_in[0]
    DIRECTION INPUT ;
    USE SIGNAL ;
    SHAPE ABUTMENT ;
    PORT
      LAYER M4 ;
      RECT 0.000 20.544 0.024 20.568 ;
    END
  END b_addr_in[0]
  PIN b_addr_in[1]
    DIRECTION INPUT ;
    USE SIGNAL ;
    SHAPE ABUTMENT ;
    PORT
      LAYER M4 ;
      RECT 0.000 20.640 0.024 20.664 ;
    END
  END b_addr_in[1]
  PIN b_addr_in[2]
    DIRECTION INPUT ;
    USE SIGNAL ;
    SHAPE ABUTMENT ;
    PORT
      LAYER M4 ;
      RECT 0.000 20.736 0.024 20.760 ;
    END
  END b_addr_in[2]
  PIN b_addr_in[3]
    DIRECTION INPUT ;
    USE SIGNAL ;
    SHAPE ABUTMENT ;
    PORT
      LAYER M4 ;
      RECT 0.000 20.832 0.024 20.856 ;
    END
  END b_addr_in[3]
  PIN b_addr_in[4]
    DIRECTION INPUT ;
    USE SIGNAL ;
    SHAPE ABUTMENT ;
    PORT
      LAYER M4 ;
      RECT 0.000 20.928 0.024 20.952 ;
    END
  END b_addr_in[4]
  PIN b_addr_in[5]
    DIRECTION INPUT ;
    USE SIGNAL ;
    SHAPE ABUTMENT ;
    PORT
      LAYER M4 ;
      RECT 0.000 21.024 0.024 21.048 ;
    END
  END b_addr_in[5]
  PIN b_addr_in[6]
    DIRECTION INPUT ;
    USE SIGNAL ;
    SHAPE ABUTMENT ;
    PORT
      LAYER M4 ;
      RECT 0.000 21.120 0.024 21.144 ;
    END
  END b_addr_in[6]
  PIN b_addr_in[7]
    DIRECTION INPUT ;
    USE SIGNAL ;
    SHAPE ABUTMENT ;
    PORT
      LAYER M4 ;
      RECT 0.000 21.216 0.024 21.240 ;
    END
  END b_addr_in[7]
  PIN b_addr_in[8]
    DIRECTION INPUT ;
    USE SIGNAL ;
    SHAPE ABUTMENT ;
    PORT
      LAYER M4 ;
      RECT 0.000 21.312 0.024 21.336 ;
    END
  END b_addr_in[8]
  PIN b_wd_in[0]
    DIRECTION INPUT ;
    USE SIGNAL ;
    SHAPE ABUTMENT ;
    PORT
      LAYER M4 ;
      RECT 0.000 21.408 0.024 21.432 ;
    END
  END b_wd_in[0]
  PIN b_wd_in[1]
    DIRECTION INPUT ;
    USE SIGNAL ;
    SHAPE ABUTMENT ;
    PORT
      LAYER M4 ;
      RECT 0.000 21.504 0.024 21.528 ;
    END
  END b_wd_in[1]
  PIN b_wd_in[2]
    DIRECTION INPUT ;
    USE SIGNAL ;
    SHAPE ABUTMENT ;
    PORT
      LAYER M4 ;
      RECT 0.000 21.600 0.024 21.624 ;
    END
  END b_wd_in[2]
  PIN b_wd_in[3]
    DIRECTION INPUT ;
    USE SIGNAL ;
    SHAPE ABUTMENT ;
    PORT
      LAYER M4 ;
      RECT 0.000 21.696 0.024 21.720 ;
    END
  END b_wd_in[3]
  PIN b_wd_in[4]
    DIRECTION INPUT ;
    USE SIGNAL ;
    SHAPE ABUTMENT ;
    PORT
      LAYER M4 ;
      RECT 130.872 0.768 130.896 0.792 ;
    END
  END b_wd_in[4]
  PIN b_wd_in[5]
    DIRECTION INPUT ;
    USE SIGNAL ;
    SHAPE ABUTMENT ;
    PORT
      LAYER M4 ;
      RECT 130.872 0.864 130.896 0.888 ;
    END
  END b_wd_in[5]
  PIN b_wd_in[6]
    DIRECTION INPUT ;
    USE SIGNAL ;
    SHAPE ABUTMENT ;
    PORT
      LAYER M4 ;
      RECT 130.872 0.960 130.896 0.984 ;
    END
  END b_wd_in[6]
  PIN b_wd_in[7]
    DIRECTION INPUT ;
    USE SIGNAL ;
    SHAPE ABUTMENT ;
    PORT
      LAYER M4 ;
      RECT 130.872 1.056 130.896 1.080 ;
    END
  END b_wd_in[7]
  PIN b_wd_in[8]
    DIRECTION INPUT ;
    USE SIGNAL ;
    SHAPE ABUTMENT ;
    PORT
      LAYER M4 ;
      RECT 130.872 1.152 130.896 1.176 ;
    END
  END b_wd_in[8]
  PIN b_wd_in[9]
    DIRECTION INPUT ;
    USE SIGNAL ;
    SHAPE ABUTMENT ;
    PORT
      LAYER M4 ;
      RECT 130.872 1.248 130.896 1.272 ;
    END
  END b_wd_in[9]
  PIN b_wd_in[10]
    DIRECTION INPUT ;
    USE SIGNAL ;
    SHAPE ABUTMENT ;
    PORT
      LAYER M4 ;
      RECT 130.872 1.344 130.896 1.368 ;
    END
  END b_wd_in[10]
  PIN b_wd_in[11]
    DIRECTION INPUT ;
    USE SIGNAL ;
    SHAPE ABUTMENT ;
    PORT
      LAYER M4 ;
      RECT 130.872 1.440 130.896 1.464 ;
    END
  END b_wd_in[11]
  PIN b_wd_in[12]
    DIRECTION INPUT ;
    USE SIGNAL ;
    SHAPE ABUTMENT ;
    PORT
      LAYER M4 ;
      RECT 130.872 1.536 130.896 1.560 ;
    END
  END b_wd_in[12]
  PIN b_wd_in[13]
    DIRECTION INPUT ;
    USE SIGNAL ;
    SHAPE ABUTMENT ;
    PORT
      LAYER M4 ;
      RECT 130.872 1.632 130.896 1.656 ;
    END
  END b_wd_in[13]
  PIN b_wd_in[14]
    DIRECTION INPUT ;
    USE SIGNAL ;
    SHAPE ABUTMENT ;
    PORT
      LAYER M4 ;
      RECT 130.872 1.728 130.896 1.752 ;
    END
  END b_wd_in[14]
  PIN b_wd_in[15]
    DIRECTION INPUT ;
    USE SIGNAL ;
    SHAPE ABUTMENT ;
    PORT
      LAYER M4 ;
      RECT 130.872 1.824 130.896 1.848 ;
    END
  END b_wd_in[15]
  PIN b_wd_in[16]
    DIRECTION INPUT ;
    USE SIGNAL ;
    SHAPE ABUTMENT ;
    PORT
      LAYER M4 ;
      RECT 130.872 1.920 130.896 1.944 ;
    END
  END b_wd_in[16]
  PIN b_wd_in[17]
    DIRECTION INPUT ;
    USE SIGNAL ;
    SHAPE ABUTMENT ;
    PORT
      LAYER M4 ;
      RECT 130.872 2.016 130.896 2.040 ;
    END
  END b_wd_in[17]
  PIN b_wd_in[18]
    DIRECTION INPUT ;
    USE SIGNAL ;
    SHAPE ABUTMENT ;
    PORT
      LAYER M4 ;
      RECT 130.872 2.112 130.896 2.136 ;
    END
  END b_wd_in[18]
  PIN b_wd_in[19]
    DIRECTION INPUT ;
    USE SIGNAL ;
    SHAPE ABUTMENT ;
    PORT
      LAYER M4 ;
      RECT 130.872 2.208 130.896 2.232 ;
    END
  END b_wd_in[19]
  PIN b_wd_in[20]
    DIRECTION INPUT ;
    USE SIGNAL ;
    SHAPE ABUTMENT ;
    PORT
      LAYER M4 ;
      RECT 130.872 2.304 130.896 2.328 ;
    END
  END b_wd_in[20]
  PIN b_wd_in[21]
    DIRECTION INPUT ;
    USE SIGNAL ;
    SHAPE ABUTMENT ;
    PORT
      LAYER M4 ;
      RECT 130.872 2.400 130.896 2.424 ;
    END
  END b_wd_in[21]
  PIN b_wd_in[22]
    DIRECTION INPUT ;
    USE SIGNAL ;
    SHAPE ABUTMENT ;
    PORT
      LAYER M4 ;
      RECT 130.872 2.496 130.896 2.520 ;
    END
  END b_wd_in[22]
  PIN b_wd_in[23]
    DIRECTION INPUT ;
    USE SIGNAL ;
    SHAPE ABUTMENT ;
    PORT
      LAYER M4 ;
      RECT 130.872 2.592 130.896 2.616 ;
    END
  END b_wd_in[23]
  PIN b_wd_in[24]
    DIRECTION INPUT ;
    USE SIGNAL ;
    SHAPE ABUTMENT ;
    PORT
      LAYER M4 ;
      RECT 130.872 2.688 130.896 2.712 ;
    END
  END b_wd_in[24]
  PIN b_wd_in[25]
    DIRECTION INPUT ;
    USE SIGNAL ;
    SHAPE ABUTMENT ;
    PORT
      LAYER M4 ;
      RECT 130.872 2.784 130.896 2.808 ;
    END
  END b_wd_in[25]
  PIN b_wd_in[26]
    DIRECTION INPUT ;
    USE SIGNAL ;
    SHAPE ABUTMENT ;
    PORT
      LAYER M4 ;
      RECT 130.872 2.880 130.896 2.904 ;
    END
  END b_wd_in[26]
  PIN b_wd_in[27]
    DIRECTION INPUT ;
    USE SIGNAL ;
    SHAPE ABUTMENT ;
    PORT
      LAYER M4 ;
      RECT 130.872 2.976 130.896 3.000 ;
    END
  END b_wd_in[27]
  PIN b_wd_in[28]
    DIRECTION INPUT ;
    USE SIGNAL ;
    SHAPE ABUTMENT ;
    PORT
      LAYER M4 ;
      RECT 130.872 3.072 130.896 3.096 ;
    END
  END b_wd_in[28]
  PIN b_wd_in[29]
    DIRECTION INPUT ;
    USE SIGNAL ;
    SHAPE ABUTMENT ;
    PORT
      LAYER M4 ;
      RECT 130.872 3.168 130.896 3.192 ;
    END
  END b_wd_in[29]
  PIN b_wd_in[30]
    DIRECTION INPUT ;
    USE SIGNAL ;
    SHAPE ABUTMENT ;
    PORT
      LAYER M4 ;
      RECT 130.872 3.264 130.896 3.288 ;
    END
  END b_wd_in[30]
  PIN b_wd_in[31]
    DIRECTION INPUT ;
    USE SIGNAL ;
    SHAPE ABUTMENT ;
    PORT
      LAYER M4 ;
      RECT 130.872 3.360 130.896 3.384 ;
    END
  END b_wd_in[31]
  PIN b_wd_in[32]
    DIRECTION INPUT ;
    USE SIGNAL ;
    SHAPE ABUTMENT ;
    PORT
      LAYER M4 ;
      RECT 130.872 3.456 130.896 3.480 ;
    END
  END b_wd_in[32]
  PIN b_wd_in[33]
    DIRECTION INPUT ;
    USE SIGNAL ;
    SHAPE ABUTMENT ;
    PORT
      LAYER M4 ;
      RECT 130.872 3.552 130.896 3.576 ;
    END
  END b_wd_in[33]
  PIN b_wd_in[34]
    DIRECTION INPUT ;
    USE SIGNAL ;
    SHAPE ABUTMENT ;
    PORT
      LAYER M4 ;
      RECT 130.872 3.648 130.896 3.672 ;
    END
  END b_wd_in[34]
  PIN b_wd_in[35]
    DIRECTION INPUT ;
    USE SIGNAL ;
    SHAPE ABUTMENT ;
    PORT
      LAYER M4 ;
      RECT 130.872 3.744 130.896 3.768 ;
    END
  END b_wd_in[35]
  PIN b_wd_in[36]
    DIRECTION INPUT ;
    USE SIGNAL ;
    SHAPE ABUTMENT ;
    PORT
      LAYER M4 ;
      RECT 130.872 3.840 130.896 3.864 ;
    END
  END b_wd_in[36]
  PIN b_wd_in[37]
    DIRECTION INPUT ;
    USE SIGNAL ;
    SHAPE ABUTMENT ;
    PORT
      LAYER M4 ;
      RECT 130.872 3.936 130.896 3.960 ;
    END
  END b_wd_in[37]
  PIN b_wd_in[38]
    DIRECTION INPUT ;
    USE SIGNAL ;
    SHAPE ABUTMENT ;
    PORT
      LAYER M4 ;
      RECT 130.872 4.032 130.896 4.056 ;
    END
  END b_wd_in[38]
  PIN b_wd_in[39]
    DIRECTION INPUT ;
    USE SIGNAL ;
    SHAPE ABUTMENT ;
    PORT
      LAYER M4 ;
      RECT 130.872 4.128 130.896 4.152 ;
    END
  END b_wd_in[39]
  PIN b_wd_in[40]
    DIRECTION INPUT ;
    USE SIGNAL ;
    SHAPE ABUTMENT ;
    PORT
      LAYER M4 ;
      RECT 130.872 4.224 130.896 4.248 ;
    END
  END b_wd_in[40]
  PIN b_wd_in[41]
    DIRECTION INPUT ;
    USE SIGNAL ;
    SHAPE ABUTMENT ;
    PORT
      LAYER M4 ;
      RECT 130.872 4.320 130.896 4.344 ;
    END
  END b_wd_in[41]
  PIN b_wd_in[42]
    DIRECTION INPUT ;
    USE SIGNAL ;
    SHAPE ABUTMENT ;
    PORT
      LAYER M4 ;
      RECT 130.872 4.416 130.896 4.440 ;
    END
  END b_wd_in[42]
  PIN b_wd_in[43]
    DIRECTION INPUT ;
    USE SIGNAL ;
    SHAPE ABUTMENT ;
    PORT
      LAYER M4 ;
      RECT 130.872 4.512 130.896 4.536 ;
    END
  END b_wd_in[43]
  PIN b_wd_in[44]
    DIRECTION INPUT ;
    USE SIGNAL ;
    SHAPE ABUTMENT ;
    PORT
      LAYER M4 ;
      RECT 130.872 4.608 130.896 4.632 ;
    END
  END b_wd_in[44]
  PIN b_wd_in[45]
    DIRECTION INPUT ;
    USE SIGNAL ;
    SHAPE ABUTMENT ;
    PORT
      LAYER M4 ;
      RECT 130.872 4.704 130.896 4.728 ;
    END
  END b_wd_in[45]
  PIN b_wd_in[46]
    DIRECTION INPUT ;
    USE SIGNAL ;
    SHAPE ABUTMENT ;
    PORT
      LAYER M4 ;
      RECT 130.872 4.800 130.896 4.824 ;
    END
  END b_wd_in[46]
  PIN b_wd_in[47]
    DIRECTION INPUT ;
    USE SIGNAL ;
    SHAPE ABUTMENT ;
    PORT
      LAYER M4 ;
      RECT 130.872 4.896 130.896 4.920 ;
    END
  END b_wd_in[47]
  PIN b_wd_in[48]
    DIRECTION INPUT ;
    USE SIGNAL ;
    SHAPE ABUTMENT ;
    PORT
      LAYER M4 ;
      RECT 130.872 4.992 130.896 5.016 ;
    END
  END b_wd_in[48]
  PIN b_wd_in[49]
    DIRECTION INPUT ;
    USE SIGNAL ;
    SHAPE ABUTMENT ;
    PORT
      LAYER M4 ;
      RECT 130.872 5.088 130.896 5.112 ;
    END
  END b_wd_in[49]
  PIN b_wd_in[50]
    DIRECTION INPUT ;
    USE SIGNAL ;
    SHAPE ABUTMENT ;
    PORT
      LAYER M4 ;
      RECT 130.872 5.184 130.896 5.208 ;
    END
  END b_wd_in[50]
  PIN b_wd_in[51]
    DIRECTION INPUT ;
    USE SIGNAL ;
    SHAPE ABUTMENT ;
    PORT
      LAYER M4 ;
      RECT 130.872 5.280 130.896 5.304 ;
    END
  END b_wd_in[51]
  PIN b_wd_in[52]
    DIRECTION INPUT ;
    USE SIGNAL ;
    SHAPE ABUTMENT ;
    PORT
      LAYER M4 ;
      RECT 130.872 5.376 130.896 5.400 ;
    END
  END b_wd_in[52]
  PIN b_wd_in[53]
    DIRECTION INPUT ;
    USE SIGNAL ;
    SHAPE ABUTMENT ;
    PORT
      LAYER M4 ;
      RECT 130.872 5.472 130.896 5.496 ;
    END
  END b_wd_in[53]
  PIN b_wd_in[54]
    DIRECTION INPUT ;
    USE SIGNAL ;
    SHAPE ABUTMENT ;
    PORT
      LAYER M4 ;
      RECT 130.872 5.568 130.896 5.592 ;
    END
  END b_wd_in[54]
  PIN b_wd_in[55]
    DIRECTION INPUT ;
    USE SIGNAL ;
    SHAPE ABUTMENT ;
    PORT
      LAYER M4 ;
      RECT 130.872 5.664 130.896 5.688 ;
    END
  END b_wd_in[55]
  PIN b_wd_in[56]
    DIRECTION INPUT ;
    USE SIGNAL ;
    SHAPE ABUTMENT ;
    PORT
      LAYER M4 ;
      RECT 130.872 5.760 130.896 5.784 ;
    END
  END b_wd_in[56]
  PIN b_wd_in[57]
    DIRECTION INPUT ;
    USE SIGNAL ;
    SHAPE ABUTMENT ;
    PORT
      LAYER M4 ;
      RECT 130.872 5.856 130.896 5.880 ;
    END
  END b_wd_in[57]
  PIN b_wd_in[58]
    DIRECTION INPUT ;
    USE SIGNAL ;
    SHAPE ABUTMENT ;
    PORT
      LAYER M4 ;
      RECT 130.872 5.952 130.896 5.976 ;
    END
  END b_wd_in[58]
  PIN b_wd_in[59]
    DIRECTION INPUT ;
    USE SIGNAL ;
    SHAPE ABUTMENT ;
    PORT
      LAYER M4 ;
      RECT 130.872 6.048 130.896 6.072 ;
    END
  END b_wd_in[59]
  PIN b_wd_in[60]
    DIRECTION INPUT ;
    USE SIGNAL ;
    SHAPE ABUTMENT ;
    PORT
      LAYER M4 ;
      RECT 130.872 6.144 130.896 6.168 ;
    END
  END b_wd_in[60]
  PIN b_wd_in[61]
    DIRECTION INPUT ;
    USE SIGNAL ;
    SHAPE ABUTMENT ;
    PORT
      LAYER M4 ;
      RECT 130.872 6.240 130.896 6.264 ;
    END
  END b_wd_in[61]
  PIN b_wd_in[62]
    DIRECTION INPUT ;
    USE SIGNAL ;
    SHAPE ABUTMENT ;
    PORT
      LAYER M4 ;
      RECT 130.872 6.336 130.896 6.360 ;
    END
  END b_wd_in[62]
  PIN b_wd_in[63]
    DIRECTION INPUT ;
    USE SIGNAL ;
    SHAPE ABUTMENT ;
    PORT
      LAYER M4 ;
      RECT 130.872 6.432 130.896 6.456 ;
    END
  END b_wd_in[63]
  PIN b_w_mask_in[0]
    DIRECTION INPUT ;
    USE SIGNAL ;
    SHAPE ABUTMENT ;
    PORT
      LAYER M4 ;
      RECT 130.872 6.528 130.896 6.552 ;
    END
  END b_w_mask_in[0]
  PIN b_w_mask_in[1]
    DIRECTION INPUT ;
    USE SIGNAL ;
    SHAPE ABUTMENT ;
    PORT
      LAYER M4 ;
      RECT 130.872 6.624 130.896 6.648 ;
    END
  END b_w_mask_in[1]
  PIN b_w_mask_in[2]
    DIRECTION INPUT ;
    USE SIGNAL ;
    SHAPE ABUTMENT ;
    PORT
      LAYER M4 ;
      RECT 130.872 6.720 130.896 6.744 ;
    END
  END b_w_mask_in[2]
  PIN b_w_mask_in[3]
    DIRECTION INPUT ;
    USE SIGNAL ;
    SHAPE ABUTMENT ;
    PORT
      LAYER M4 ;
      RECT 130.872 6.816 130.896 6.840 ;
    END
  END b_w_mask_in[3]
  PIN b_w_mask_in[4]
    DIRECTION INPUT ;
    USE SIGNAL ;
    SHAPE ABUTMENT ;
    PORT
      LAYER M4 ;
      RECT 130.872 6.912 130.896 6.936 ;
    END
  END b_w_mask_in[4]
  PIN b_w_mask_in[5]
    DIRECTION INPUT ;
    USE SIGNAL ;
    SHAPE ABUTMENT ;
    PORT
      LAYER M4 ;
      RECT 130.872 7.008 130.896 7.032 ;
    END
  END b_w_mask_in[5]
  PIN b_w_mask_in[6]
    DIRECTION INPUT ;
    USE SIGNAL ;
    SHAPE ABUTMENT ;
    PORT
      LAYER M4 ;
      RECT 130.872 7.104 130.896 7.128 ;
    END
  END b_w_mask_in[6]
  PIN b_w_mask_in[7]
    DIRECTION INPUT ;
    USE SIGNAL ;
    SHAPE ABUTMENT ;
    PORT
      LAYER M4 ;
      RECT 130.872 7.200 130.896 7.224 ;
    END
  END b_w_mask_in[7]
  PIN b_w_mask_in[8]
    DIRECTION INPUT ;
    USE SIGNAL ;
    SHAPE ABUTMENT ;
    PORT
      LAYER M4 ;
      RECT 130.872 7.296 130.896 7.320 ;
    END
  END b_w_mask_in[8]
  PIN b_w_mask_in[9]
    DIRECTION INPUT ;
    USE SIGNAL ;
    SHAPE ABUTMENT ;
    PORT
      LAYER M4 ;
      RECT 130.872 7.392 130.896 7.416 ;
    END
  END b_w_mask_in[9]
  PIN b_w_mask_in[10]
    DIRECTION INPUT ;
    USE SIGNAL ;
    SHAPE ABUTMENT ;
    PORT
      LAYER M4 ;
      RECT 130.872 7.488 130.896 7.512 ;
    END
  END b_w_mask_in[10]
  PIN b_w_mask_in[11]
    DIRECTION INPUT ;
    USE SIGNAL ;
    SHAPE ABUTMENT ;
    PORT
      LAYER M4 ;
      RECT 130.872 7.584 130.896 7.608 ;
    END
  END b_w_mask_in[11]
  PIN b_w_mask_in[12]
    DIRECTION INPUT ;
    USE SIGNAL ;
    SHAPE ABUTMENT ;
    PORT
      LAYER M4 ;
      RECT 130.872 7.680 130.896 7.704 ;
    END
  END b_w_mask_in[12]
  PIN b_w_mask_in[13]
    DIRECTION INPUT ;
    USE SIGNAL ;
    SHAPE ABUTMENT ;
    PORT
      LAYER M4 ;
      RECT 130.872 7.776 130.896 7.800 ;
    END
  END b_w_mask_in[13]
  PIN b_w_mask_in[14]
    DIRECTION INPUT ;
    USE SIGNAL ;
    SHAPE ABUTMENT ;
    PORT
      LAYER M4 ;
      RECT 130.872 7.872 130.896 7.896 ;
    END
  END b_w_mask_in[14]
  PIN b_w_mask_in[15]
    DIRECTION INPUT ;
    USE SIGNAL ;
    SHAPE ABUTMENT ;
    PORT
      LAYER M4 ;
      RECT 130.872 7.968 130.896 7.992 ;
    END
  END b_w_mask_in[15]
  PIN b_w_mask_in[16]
    DIRECTION INPUT ;
    USE SIGNAL ;
    SHAPE ABUTMENT ;
    PORT
      LAYER M4 ;
      RECT 130.872 8.064 130.896 8.088 ;
    END
  END b_w_mask_in[16]
  PIN b_w_mask_in[17]
    DIRECTION INPUT ;
    USE SIGNAL ;
    SHAPE ABUTMENT ;
    PORT
      LAYER M4 ;
      RECT 130.872 8.160 130.896 8.184 ;
    END
  END b_w_mask_in[17]
  PIN b_w_mask_in[18]
    DIRECTION INPUT ;
    USE SIGNAL ;
    SHAPE ABUTMENT ;
    PORT
      LAYER M4 ;
      RECT 130.872 8.256 130.896 8.280 ;
    END
  END b_w_mask_in[18]
  PIN b_w_mask_in[19]
    DIRECTION INPUT ;
    USE SIGNAL ;
    SHAPE ABUTMENT ;
    PORT
      LAYER M4 ;
      RECT 130.872 8.352 130.896 8.376 ;
    END
  END b_w_mask_in[19]
  PIN b_w_mask_in[20]
    DIRECTION INPUT ;
    USE SIGNAL ;
    SHAPE ABUTMENT ;
    PORT
      LAYER M4 ;
      RECT 130.872 8.448 130.896 8.472 ;
    END
  END b_w_mask_in[20]
  PIN b_w_mask_in[21]
    DIRECTION INPUT ;
    USE SIGNAL ;
    SHAPE ABUTMENT ;
    PORT
      LAYER M4 ;
      RECT 130.872 8.544 130.896 8.568 ;
    END
  END b_w_mask_in[21]
  PIN b_w_mask_in[22]
    DIRECTION INPUT ;
    USE SIGNAL ;
    SHAPE ABUTMENT ;
    PORT
      LAYER M4 ;
      RECT 130.872 8.640 130.896 8.664 ;
    END
  END b_w_mask_in[22]
  PIN b_w_mask_in[23]
    DIRECTION INPUT ;
    USE SIGNAL ;
    SHAPE ABUTMENT ;
    PORT
      LAYER M4 ;
      RECT 130.872 8.736 130.896 8.760 ;
    END
  END b_w_mask_in[23]
  PIN b_w_mask_in[24]
    DIRECTION INPUT ;
    USE SIGNAL ;
    SHAPE ABUTMENT ;
    PORT
      LAYER M4 ;
      RECT 130.872 8.832 130.896 8.856 ;
    END
  END b_w_mask_in[24]
  PIN b_w_mask_in[25]
    DIRECTION INPUT ;
    USE SIGNAL ;
    SHAPE ABUTMENT ;
    PORT
      LAYER M4 ;
      RECT 130.872 8.928 130.896 8.952 ;
    END
  END b_w_mask_in[25]
  PIN b_w_mask_in[26]
    DIRECTION INPUT ;
    USE SIGNAL ;
    SHAPE ABUTMENT ;
    PORT
      LAYER M4 ;
      RECT 130.872 9.024 130.896 9.048 ;
    END
  END b_w_mask_in[26]
  PIN b_w_mask_in[27]
    DIRECTION INPUT ;
    USE SIGNAL ;
    SHAPE ABUTMENT ;
    PORT
      LAYER M4 ;
      RECT 130.872 9.120 130.896 9.144 ;
    END
  END b_w_mask_in[27]
  PIN b_w_mask_in[28]
    DIRECTION INPUT ;
    USE SIGNAL ;
    SHAPE ABUTMENT ;
    PORT
      LAYER M4 ;
      RECT 130.872 9.216 130.896 9.240 ;
    END
  END b_w_mask_in[28]
  PIN b_w_mask_in[29]
    DIRECTION INPUT ;
    USE SIGNAL ;
    SHAPE ABUTMENT ;
    PORT
      LAYER M4 ;
      RECT 130.872 9.312 130.896 9.336 ;
    END
  END b_w_mask_in[29]
  PIN b_w_mask_in[30]
    DIRECTION INPUT ;
    USE SIGNAL ;
    SHAPE ABUTMENT ;
    PORT
      LAYER M4 ;
      RECT 130.872 9.408 130.896 9.432 ;
    END
  END b_w_mask_in[30]
  PIN b_w_mask_in[31]
    DIRECTION INPUT ;
    USE SIGNAL ;
    SHAPE ABUTMENT ;
    PORT
      LAYER M4 ;
      RECT 130.872 9.504 130.896 9.528 ;
    END
  END b_w_mask_in[31]
  PIN b_w_mask_in[32]
    DIRECTION INPUT ;
    USE SIGNAL ;
    SHAPE ABUTMENT ;
    PORT
      LAYER M4 ;
      RECT 130.872 9.600 130.896 9.624 ;
    END
  END b_w_mask_in[32]
  PIN b_w_mask_in[33]
    DIRECTION INPUT ;
    USE SIGNAL ;
    SHAPE ABUTMENT ;
    PORT
      LAYER M4 ;
      RECT 130.872 9.696 130.896 9.720 ;
    END
  END b_w_mask_in[33]
  PIN b_w_mask_in[34]
    DIRECTION INPUT ;
    USE SIGNAL ;
    SHAPE ABUTMENT ;
    PORT
      LAYER M4 ;
      RECT 130.872 9.792 130.896 9.816 ;
    END
  END b_w_mask_in[34]
  PIN b_w_mask_in[35]
    DIRECTION INPUT ;
    USE SIGNAL ;
    SHAPE ABUTMENT ;
    PORT
      LAYER M4 ;
      RECT 130.872 9.888 130.896 9.912 ;
    END
  END b_w_mask_in[35]
  PIN b_w_mask_in[36]
    DIRECTION INPUT ;
    USE SIGNAL ;
    SHAPE ABUTMENT ;
    PORT
      LAYER M4 ;
      RECT 130.872 9.984 130.896 10.008 ;
    END
  END b_w_mask_in[36]
  PIN b_w_mask_in[37]
    DIRECTION INPUT ;
    USE SIGNAL ;
    SHAPE ABUTMENT ;
    PORT
      LAYER M4 ;
      RECT 130.872 10.080 130.896 10.104 ;
    END
  END b_w_mask_in[37]
  PIN b_w_mask_in[38]
    DIRECTION INPUT ;
    USE SIGNAL ;
    SHAPE ABUTMENT ;
    PORT
      LAYER M4 ;
      RECT 130.872 10.176 130.896 10.200 ;
    END
  END b_w_mask_in[38]
  PIN b_w_mask_in[39]
    DIRECTION INPUT ;
    USE SIGNAL ;
    SHAPE ABUTMENT ;
    PORT
      LAYER M4 ;
      RECT 130.872 10.272 130.896 10.296 ;
    END
  END b_w_mask_in[39]
  PIN b_w_mask_in[40]
    DIRECTION INPUT ;
    USE SIGNAL ;
    SHAPE ABUTMENT ;
    PORT
      LAYER M4 ;
      RECT 130.872 10.368 130.896 10.392 ;
    END
  END b_w_mask_in[40]
  PIN b_w_mask_in[41]
    DIRECTION INPUT ;
    USE SIGNAL ;
    SHAPE ABUTMENT ;
    PORT
      LAYER M4 ;
      RECT 130.872 10.464 130.896 10.488 ;
    END
  END b_w_mask_in[41]
  PIN b_w_mask_in[42]
    DIRECTION INPUT ;
    USE SIGNAL ;
    SHAPE ABUTMENT ;
    PORT
      LAYER M4 ;
      RECT 130.872 10.560 130.896 10.584 ;
    END
  END b_w_mask_in[42]
  PIN b_w_mask_in[43]
    DIRECTION INPUT ;
    USE SIGNAL ;
    SHAPE ABUTMENT ;
    PORT
      LAYER M4 ;
      RECT 130.872 10.656 130.896 10.680 ;
    END
  END b_w_mask_in[43]
  PIN b_w_mask_in[44]
    DIRECTION INPUT ;
    USE SIGNAL ;
    SHAPE ABUTMENT ;
    PORT
      LAYER M4 ;
      RECT 130.872 10.752 130.896 10.776 ;
    END
  END b_w_mask_in[44]
  PIN b_w_mask_in[45]
    DIRECTION INPUT ;
    USE SIGNAL ;
    SHAPE ABUTMENT ;
    PORT
      LAYER M4 ;
      RECT 130.872 10.848 130.896 10.872 ;
    END
  END b_w_mask_in[45]
  PIN b_w_mask_in[46]
    DIRECTION INPUT ;
    USE SIGNAL ;
    SHAPE ABUTMENT ;
    PORT
      LAYER M4 ;
      RECT 130.872 10.944 130.896 10.968 ;
    END
  END b_w_mask_in[46]
  PIN b_w_mask_in[47]
    DIRECTION INPUT ;
    USE SIGNAL ;
    SHAPE ABUTMENT ;
    PORT
      LAYER M4 ;
      RECT 130.872 11.040 130.896 11.064 ;
    END
  END b_w_mask_in[47]
  PIN b_w_mask_in[48]
    DIRECTION INPUT ;
    USE SIGNAL ;
    SHAPE ABUTMENT ;
    PORT
      LAYER M4 ;
      RECT 130.872 11.136 130.896 11.160 ;
    END
  END b_w_mask_in[48]
  PIN b_w_mask_in[49]
    DIRECTION INPUT ;
    USE SIGNAL ;
    SHAPE ABUTMENT ;
    PORT
      LAYER M4 ;
      RECT 130.872 11.232 130.896 11.256 ;
    END
  END b_w_mask_in[49]
  PIN b_w_mask_in[50]
    DIRECTION INPUT ;
    USE SIGNAL ;
    SHAPE ABUTMENT ;
    PORT
      LAYER M4 ;
      RECT 130.872 11.328 130.896 11.352 ;
    END
  END b_w_mask_in[50]
  PIN b_w_mask_in[51]
    DIRECTION INPUT ;
    USE SIGNAL ;
    SHAPE ABUTMENT ;
    PORT
      LAYER M4 ;
      RECT 130.872 11.424 130.896 11.448 ;
    END
  END b_w_mask_in[51]
  PIN b_w_mask_in[52]
    DIRECTION INPUT ;
    USE SIGNAL ;
    SHAPE ABUTMENT ;
    PORT
      LAYER M4 ;
      RECT 130.872 11.520 130.896 11.544 ;
    END
  END b_w_mask_in[52]
  PIN b_w_mask_in[53]
    DIRECTION INPUT ;
    USE SIGNAL ;
    SHAPE ABUTMENT ;
    PORT
      LAYER M4 ;
      RECT 130.872 11.616 130.896 11.640 ;
    END
  END b_w_mask_in[53]
  PIN b_w_mask_in[54]
    DIRECTION INPUT ;
    USE SIGNAL ;
    SHAPE ABUTMENT ;
    PORT
      LAYER M4 ;
      RECT 130.872 11.712 130.896 11.736 ;
    END
  END b_w_mask_in[54]
  PIN b_w_mask_in[55]
    DIRECTION INPUT ;
    USE SIGNAL ;
    SHAPE ABUTMENT ;
    PORT
      LAYER M4 ;
      RECT 130.872 11.808 130.896 11.832 ;
    END
  END b_w_mask_in[55]
  PIN b_w_mask_in[56]
    DIRECTION INPUT ;
    USE SIGNAL ;
    SHAPE ABUTMENT ;
    PORT
      LAYER M4 ;
      RECT 130.872 11.904 130.896 11.928 ;
    END
  END b_w_mask_in[56]
  PIN b_w_mask_in[57]
    DIRECTION INPUT ;
    USE SIGNAL ;
    SHAPE ABUTMENT ;
    PORT
      LAYER M4 ;
      RECT 130.872 12.000 130.896 12.024 ;
    END
  END b_w_mask_in[57]
  PIN b_w_mask_in[58]
    DIRECTION INPUT ;
    USE SIGNAL ;
    SHAPE ABUTMENT ;
    PORT
      LAYER M4 ;
      RECT 130.872 12.096 130.896 12.120 ;
    END
  END b_w_mask_in[58]
  PIN b_w_mask_in[59]
    DIRECTION INPUT ;
    USE SIGNAL ;
    SHAPE ABUTMENT ;
    PORT
      LAYER M4 ;
      RECT 130.872 12.192 130.896 12.216 ;
    END
  END b_w_mask_in[59]
  PIN b_w_mask_in[60]
    DIRECTION INPUT ;
    USE SIGNAL ;
    SHAPE ABUTMENT ;
    PORT
      LAYER M4 ;
      RECT 130.872 12.288 130.896 12.312 ;
    END
  END b_w_mask_in[60]
  PIN b_w_mask_in[61]
    DIRECTION INPUT ;
    USE SIGNAL ;
    SHAPE ABUTMENT ;
    PORT
      LAYER M4 ;
      RECT 130.872 12.384 130.896 12.408 ;
    END
  END b_w_mask_in[61]
  PIN b_w_mask_in[62]
    DIRECTION INPUT ;
    USE SIGNAL ;
    SHAPE ABUTMENT ;
    PORT
      LAYER M4 ;
      RECT 130.872 12.480 130.896 12.504 ;
    END
  END b_w_mask_in[62]
  PIN b_w_mask_in[63]
    DIRECTION INPUT ;
    USE SIGNAL ;
    SHAPE ABUTMENT ;
    PORT
      LAYER M4 ;
      RECT 130.872 12.576 130.896 12.600 ;
    END
  END b_w_mask_in[63]
  PIN b_rd_out[0]
    DIRECTION OUTPUT ;
    USE SIGNAL ;
    SHAPE ABUTMENT ;
    PORT
      LAYER M4 ;
      RECT 130.872 12.672 130.896 12.696 ;
    END
  END b_rd_out[0]
  PIN b_rd_out[1]
    DIRECTION OUTPUT ;
    USE SIGNAL ;
    SHAPE ABUTMENT ;
    PORT
      LAYER M4 ;
      RECT 130.872 12.768 130.896 12.792 ;
    END
  END b_rd_out[1]
  PIN b_rd_out[2]
    DIRECTION OUTPUT ;
    USE SIGNAL ;
    SHAPE ABUTMENT ;
    PORT
      LAYER M4 ;
      RECT 130.872 12.864 130.896 12.888 ;
    END
  END b_rd_out[2]
  PIN b_rd_out[3]
    DIRECTION OUTPUT ;
    USE SIGNAL ;
    SHAPE ABUTMENT ;
    PORT
      LAYER M4 ;
      RECT 130.872 12.960 130.896 12.984 ;
    END
  END b_rd_out[3]
  PIN b_rd_out[4]
    DIRECTION OUTPUT ;
    USE SIGNAL ;
    SHAPE ABUTMENT ;
    PORT
      LAYER M4 ;
      RECT 130.872 13.056 130.896 13.080 ;
    END
  END b_rd_out[4]
  PIN b_rd_out[5]
    DIRECTION OUTPUT ;
    USE SIGNAL ;
    SHAPE ABUTMENT ;
    PORT
      LAYER M4 ;
      RECT 130.872 13.152 130.896 13.176 ;
    END
  END b_rd_out[5]
  PIN b_rd_out[6]
    DIRECTION OUTPUT ;
    USE SIGNAL ;
    SHAPE ABUTMENT ;
    PORT
      LAYER M4 ;
      RECT 130.872 13.248 130.896 13.272 ;
    END
  END b_rd_out[6]
  PIN b_rd_out[7]
    DIRECTION OUTPUT ;
    USE SIGNAL ;
    SHAPE ABUTMENT ;
    PORT
      LAYER M4 ;
      RECT 130.872 13.344 130.896 13.368 ;
    END
  END b_rd_out[7]
  PIN b_rd_out[8]
    DIRECTION OUTPUT ;
    USE SIGNAL ;
    SHAPE ABUTMENT ;
    PORT
      LAYER M4 ;
      RECT 130.872 13.440 130.896 13.464 ;
    END
  END b_rd_out[8]
  PIN b_rd_out[9]
    DIRECTION OUTPUT ;
    USE SIGNAL ;
    SHAPE ABUTMENT ;
    PORT
      LAYER M4 ;
      RECT 130.872 13.536 130.896 13.560 ;
    END
  END b_rd_out[9]
  PIN b_rd_out[10]
    DIRECTION OUTPUT ;
    USE SIGNAL ;
    SHAPE ABUTMENT ;
    PORT
      LAYER M4 ;
      RECT 130.872 13.632 130.896 13.656 ;
    END
  END b_rd_out[10]
  PIN b_rd_out[11]
    DIRECTION OUTPUT ;
    USE SIGNAL ;
    SHAPE ABUTMENT ;
    PORT
      LAYER M4 ;
      RECT 130.872 13.728 130.896 13.752 ;
    END
  END b_rd_out[11]
  PIN b_rd_out[12]
    DIRECTION OUTPUT ;
    USE SIGNAL ;
    SHAPE ABUTMENT ;
    PORT
      LAYER M4 ;
      RECT 130.872 13.824 130.896 13.848 ;
    END
  END b_rd_out[12]
  PIN b_rd_out[13]
    DIRECTION OUTPUT ;
    USE SIGNAL ;
    SHAPE ABUTMENT ;
    PORT
      LAYER M4 ;
      RECT 130.872 13.920 130.896 13.944 ;
    END
  END b_rd_out[13]
  PIN b_rd_out[14]
    DIRECTION OUTPUT ;
    USE SIGNAL ;
    SHAPE ABUTMENT ;
    PORT
      LAYER M4 ;
      RECT 130.872 14.016 130.896 14.040 ;
    END
  END b_rd_out[14]
  PIN b_rd_out[15]
    DIRECTION OUTPUT ;
    USE SIGNAL ;
    SHAPE ABUTMENT ;
    PORT
      LAYER M4 ;
      RECT 130.872 14.112 130.896 14.136 ;
    END
  END b_rd_out[15]
  PIN b_rd_out[16]
    DIRECTION OUTPUT ;
    USE SIGNAL ;
    SHAPE ABUTMENT ;
    PORT
      LAYER M4 ;
      RECT 130.872 14.208 130.896 14.232 ;
    END
  END b_rd_out[16]
  PIN b_rd_out[17]
    DIRECTION OUTPUT ;
    USE SIGNAL ;
    SHAPE ABUTMENT ;
    PORT
      LAYER M4 ;
      RECT 130.872 14.304 130.896 14.328 ;
    END
  END b_rd_out[17]
  PIN b_rd_out[18]
    DIRECTION OUTPUT ;
    USE SIGNAL ;
    SHAPE ABUTMENT ;
    PORT
      LAYER M4 ;
      RECT 130.872 14.400 130.896 14.424 ;
    END
  END b_rd_out[18]
  PIN b_rd_out[19]
    DIRECTION OUTPUT ;
    USE SIGNAL ;
    SHAPE ABUTMENT ;
    PORT
      LAYER M4 ;
      RECT 130.872 14.496 130.896 14.520 ;
    END
  END b_rd_out[19]
  PIN b_rd_out[20]
    DIRECTION OUTPUT ;
    USE SIGNAL ;
    SHAPE ABUTMENT ;
    PORT
      LAYER M4 ;
      RECT 130.872 14.592 130.896 14.616 ;
    END
  END b_rd_out[20]
  PIN b_rd_out[21]
    DIRECTION OUTPUT ;
    USE SIGNAL ;
    SHAPE ABUTMENT ;
    PORT
      LAYER M4 ;
      RECT 130.872 14.688 130.896 14.712 ;
    END
  END b_rd_out[21]
  PIN b_rd_out[22]
    DIRECTION OUTPUT ;
    USE SIGNAL ;
    SHAPE ABUTMENT ;
    PORT
      LAYER M4 ;
      RECT 130.872 14.784 130.896 14.808 ;
    END
  END b_rd_out[22]
  PIN b_rd_out[23]
    DIRECTION OUTPUT ;
    USE SIGNAL ;
    SHAPE ABUTMENT ;
    PORT
      LAYER M4 ;
      RECT 130.872 14.880 130.896 14.904 ;
    END
  END b_rd_out[23]
  PIN b_rd_out[24]
    DIRECTION OUTPUT ;
    USE SIGNAL ;
    SHAPE ABUTMENT ;
    PORT
      LAYER M4 ;
      RECT 130.872 14.976 130.896 15.000 ;
    END
  END b_rd_out[24]
  PIN b_rd_out[25]
    DIRECTION OUTPUT ;
    USE SIGNAL ;
    SHAPE ABUTMENT ;
    PORT
      LAYER M4 ;
      RECT 130.872 15.072 130.896 15.096 ;
    END
  END b_rd_out[25]
  PIN b_rd_out[26]
    DIRECTION OUTPUT ;
    USE SIGNAL ;
    SHAPE ABUTMENT ;
    PORT
      LAYER M4 ;
      RECT 130.872 15.168 130.896 15.192 ;
    END
  END b_rd_out[26]
  PIN b_rd_out[27]
    DIRECTION OUTPUT ;
    USE SIGNAL ;
    SHAPE ABUTMENT ;
    PORT
      LAYER M4 ;
      RECT 130.872 15.264 130.896 15.288 ;
    END
  END b_rd_out[27]
  PIN b_rd_out[28]
    DIRECTION OUTPUT ;
    USE SIGNAL ;
    SHAPE ABUTMENT ;
    PORT
      LAYER M4 ;
      RECT 130.872 15.360 130.896 15.384 ;
    END
  END b_rd_out[28]
  PIN b_rd_out[29]
    DIRECTION OUTPUT ;
    USE SIGNAL ;
    SHAPE ABUTMENT ;
    PORT
      LAYER M4 ;
      RECT 130.872 15.456 130.896 15.480 ;
    END
  END b_rd_out[29]
  PIN b_rd_out[30]
    DIRECTION OUTPUT ;
    USE SIGNAL ;
    SHAPE ABUTMENT ;
    PORT
      LAYER M4 ;
      RECT 130.872 15.552 130.896 15.576 ;
    END
  END b_rd_out[30]
  PIN b_rd_out[31]
    DIRECTION OUTPUT ;
    USE SIGNAL ;
    SHAPE ABUTMENT ;
    PORT
      LAYER M4 ;
      RECT 130.872 15.648 130.896 15.672 ;
    END
  END b_rd_out[31]
  PIN b_rd_out[32]
    DIRECTION OUTPUT ;
    USE SIGNAL ;
    SHAPE ABUTMENT ;
    PORT
      LAYER M4 ;
      RECT 130.872 15.744 130.896 15.768 ;
    END
  END b_rd_out[32]
  PIN b_rd_out[33]
    DIRECTION OUTPUT ;
    USE SIGNAL ;
    SHAPE ABUTMENT ;
    PORT
      LAYER M4 ;
      RECT 130.872 15.840 130.896 15.864 ;
    END
  END b_rd_out[33]
  PIN b_rd_out[34]
    DIRECTION OUTPUT ;
    USE SIGNAL ;
    SHAPE ABUTMENT ;
    PORT
      LAYER M4 ;
      RECT 130.872 15.936 130.896 15.960 ;
    END
  END b_rd_out[34]
  PIN b_rd_out[35]
    DIRECTION OUTPUT ;
    USE SIGNAL ;
    SHAPE ABUTMENT ;
    PORT
      LAYER M4 ;
      RECT 130.872 16.032 130.896 16.056 ;
    END
  END b_rd_out[35]
  PIN b_rd_out[36]
    DIRECTION OUTPUT ;
    USE SIGNAL ;
    SHAPE ABUTMENT ;
    PORT
      LAYER M4 ;
      RECT 130.872 16.128 130.896 16.152 ;
    END
  END b_rd_out[36]
  PIN b_rd_out[37]
    DIRECTION OUTPUT ;
    USE SIGNAL ;
    SHAPE ABUTMENT ;
    PORT
      LAYER M4 ;
      RECT 130.872 16.224 130.896 16.248 ;
    END
  END b_rd_out[37]
  PIN b_rd_out[38]
    DIRECTION OUTPUT ;
    USE SIGNAL ;
    SHAPE ABUTMENT ;
    PORT
      LAYER M4 ;
      RECT 130.872 16.320 130.896 16.344 ;
    END
  END b_rd_out[38]
  PIN b_rd_out[39]
    DIRECTION OUTPUT ;
    USE SIGNAL ;
    SHAPE ABUTMENT ;
    PORT
      LAYER M4 ;
      RECT 130.872 16.416 130.896 16.440 ;
    END
  END b_rd_out[39]
  PIN b_rd_out[40]
    DIRECTION OUTPUT ;
    USE SIGNAL ;
    SHAPE ABUTMENT ;
    PORT
      LAYER M4 ;
      RECT 130.872 16.512 130.896 16.536 ;
    END
  END b_rd_out[40]
  PIN b_rd_out[41]
    DIRECTION OUTPUT ;
    USE SIGNAL ;
    SHAPE ABUTMENT ;
    PORT
      LAYER M4 ;
      RECT 130.872 16.608 130.896 16.632 ;
    END
  END b_rd_out[41]
  PIN b_rd_out[42]
    DIRECTION OUTPUT ;
    USE SIGNAL ;
    SHAPE ABUTMENT ;
    PORT
      LAYER M4 ;
      RECT 130.872 16.704 130.896 16.728 ;
    END
  END b_rd_out[42]
  PIN b_rd_out[43]
    DIRECTION OUTPUT ;
    USE SIGNAL ;
    SHAPE ABUTMENT ;
    PORT
      LAYER M4 ;
      RECT 130.872 16.800 130.896 16.824 ;
    END
  END b_rd_out[43]
  PIN b_rd_out[44]
    DIRECTION OUTPUT ;
    USE SIGNAL ;
    SHAPE ABUTMENT ;
    PORT
      LAYER M4 ;
      RECT 130.872 16.896 130.896 16.920 ;
    END
  END b_rd_out[44]
  PIN b_rd_out[45]
    DIRECTION OUTPUT ;
    USE SIGNAL ;
    SHAPE ABUTMENT ;
    PORT
      LAYER M4 ;
      RECT 130.872 16.992 130.896 17.016 ;
    END
  END b_rd_out[45]
  PIN b_rd_out[46]
    DIRECTION OUTPUT ;
    USE SIGNAL ;
    SHAPE ABUTMENT ;
    PORT
      LAYER M4 ;
      RECT 130.872 17.088 130.896 17.112 ;
    END
  END b_rd_out[46]
  PIN b_rd_out[47]
    DIRECTION OUTPUT ;
    USE SIGNAL ;
    SHAPE ABUTMENT ;
    PORT
      LAYER M4 ;
      RECT 130.872 17.184 130.896 17.208 ;
    END
  END b_rd_out[47]
  PIN b_rd_out[48]
    DIRECTION OUTPUT ;
    USE SIGNAL ;
    SHAPE ABUTMENT ;
    PORT
      LAYER M4 ;
      RECT 130.872 17.280 130.896 17.304 ;
    END
  END b_rd_out[48]
  PIN b_rd_out[49]
    DIRECTION OUTPUT ;
    USE SIGNAL ;
    SHAPE ABUTMENT ;
    PORT
      LAYER M4 ;
      RECT 130.872 17.376 130.896 17.400 ;
    END
  END b_rd_out[49]
  PIN b_rd_out[50]
    DIRECTION OUTPUT ;
    USE SIGNAL ;
    SHAPE ABUTMENT ;
    PORT
      LAYER M4 ;
      RECT 130.872 17.472 130.896 17.496 ;
    END
  END b_rd_out[50]
  PIN b_rd_out[51]
    DIRECTION OUTPUT ;
    USE SIGNAL ;
    SHAPE ABUTMENT ;
    PORT
      LAYER M4 ;
      RECT 130.872 17.568 130.896 17.592 ;
    END
  END b_rd_out[51]
  PIN b_rd_out[52]
    DIRECTION OUTPUT ;
    USE SIGNAL ;
    SHAPE ABUTMENT ;
    PORT
      LAYER M4 ;
      RECT 130.872 17.664 130.896 17.688 ;
    END
  END b_rd_out[52]
  PIN b_rd_out[53]
    DIRECTION OUTPUT ;
    USE SIGNAL ;
    SHAPE ABUTMENT ;
    PORT
      LAYER M4 ;
      RECT 130.872 17.760 130.896 17.784 ;
    END
  END b_rd_out[53]
  PIN b_rd_out[54]
    DIRECTION OUTPUT ;
    USE SIGNAL ;
    SHAPE ABUTMENT ;
    PORT
      LAYER M4 ;
      RECT 130.872 17.856 130.896 17.880 ;
    END
  END b_rd_out[54]
  PIN b_rd_out[55]
    DIRECTION OUTPUT ;
    USE SIGNAL ;
    SHAPE ABUTMENT ;
    PORT
      LAYER M4 ;
      RECT 130.872 17.952 130.896 17.976 ;
    END
  END b_rd_out[55]
  PIN b_rd_out[56]
    DIRECTION OUTPUT ;
    USE SIGNAL ;
    SHAPE ABUTMENT ;
    PORT
      LAYER M4 ;
      RECT 130.872 18.048 130.896 18.072 ;
    END
  END b_rd_out[56]
  PIN b_rd_out[57]
    DIRECTION OUTPUT ;
    USE SIGNAL ;
    SHAPE ABUTMENT ;
    PORT
      LAYER M4 ;
      RECT 130.872 18.144 130.896 18.168 ;
    END
  END b_rd_out[57]
  PIN b_rd_out[58]
    DIRECTION OUTPUT ;
    USE SIGNAL ;
    SHAPE ABUTMENT ;
    PORT
      LAYER M4 ;
      RECT 130.872 18.240 130.896 18.264 ;
    END
  END b_rd_out[58]
  PIN b_rd_out[59]
    DIRECTION OUTPUT ;
    USE SIGNAL ;
    SHAPE ABUTMENT ;
    PORT
      LAYER M4 ;
      RECT 130.872 18.336 130.896 18.360 ;
    END
  END b_rd_out[59]
  PIN b_rd_out[60]
    DIRECTION OUTPUT ;
    USE SIGNAL ;
    SHAPE ABUTMENT ;
    PORT
      LAYER M4 ;
      RECT 130.872 18.432 130.896 18.456 ;
    END
  END b_rd_out[60]
  PIN b_rd_out[61]
    DIRECTION OUTPUT ;
    USE SIGNAL ;
    SHAPE ABUTMENT ;
    PORT
      LAYER M4 ;
      RECT 130.872 18.528 130.896 18.552 ;
    END
  END b_rd_out[61]
  PIN b_rd_out[62]
    DIRECTION OUTPUT ;
    USE SIGNAL ;
    SHAPE ABUTMENT ;
    PORT
      LAYER M4 ;
      RECT 130.872 18.624 130.896 18.648 ;
    END
  END b_rd_out[62]
  PIN b_rd_out[63]
    DIRECTION OUTPUT ;
    USE SIGNAL ;
    SHAPE ABUTMENT ;
    PORT
      LAYER M4 ;
      RECT 130.872 18.720 130.896 18.744 ;
    END
  END b_rd_out[63]
  PIN rr_en[0]
    DIRECTION INPUT ;
    USE SIGNAL ;
    SHAPE ABUTMENT ;
    PORT
      LAYER M4 ;
      RECT 130.872 18.816 130.896 18.840 ;
    END
  END rr_en[0]
  PIN rr_en[1]
    DIRECTION INPUT ;
    USE SIGNAL ;
    SHAPE ABUTMENT ;
    PORT
      LAYER M4 ;
      RECT 130.872 18.912 130.896 18.936 ;
    END
  END rr_en[1]
  PIN rr_addr[0]
    DIRECTION INPUT ;
    USE SIGNAL ;
    SHAPE ABUTMENT ;
    PORT
      LAYER M4 ;
      RECT 130.872 19.008 130.896 19.032 ;
    END
  END rr_addr[0]
  PIN rr_addr[1]
    DIRECTION INPUT ;
    USE SIGNAL ;
    SHAPE ABUTMENT ;
    PORT
      LAYER M4 ;
      RECT 130.872 19.104 130.896 19.128 ;
    END
  END rr_addr[1]
  PIN rr_addr[2]
    DIRECTION INPUT ;
    USE SIGNAL ;
    SHAPE ABUTMENT ;
    PORT
      LAYER M4 ;
      RECT 130.872 19.200 130.896 19.224 ;
    END
  END rr_addr[2]
  PIN rr_addr[3]
    DIRECTION INPUT ;
    USE SIGNAL ;
    SHAPE ABUTMENT ;
    PORT
      LAYER M4 ;
      RECT 130.872 19.296 130.896 19.320 ;
    END
  END rr_addr[3]
  PIN rr_addr[4]
    DIRECTION INPUT ;
    USE SIGNAL ;
    SHAPE ABUTMENT ;
    PORT
      LAYER M4 ;
      RECT 130.872 19.392 130.896 19.416 ;
    END
  END rr_addr[4]
  PIN rr_addr[5]
    DIRECTION INPUT ;
    USE SIGNAL ;
    SHAPE ABUTMENT ;
    PORT
      LAYER M4 ;
      RECT 130.872 19.488 130.896 19.512 ;
    END
  END rr_addr[5]
  PIN rr_addr[6]
    DIRECTION INPUT ;
    USE SIGNAL ;
    SHAPE ABUTMENT ;
    PORT
      LAYER M4 ;
      RECT 130.872 19.584 130.896 19.608 ;
    END
  END rr_addr[6]
  PIN rr_addr[7]
    DIRECTION INPUT ;
    USE SIGNAL ;
    SHAPE ABUTMENT ;
    PORT
      LAYER M4 ;
      RECT 130.872 19.680 130.896 19.704 ;
    END
  END rr_addr[7]
  PIN rr_addr[8]
    DIRECTION INPUT ;
    USE SIGNAL ;
    SHAPE ABUTMENT ;
    PORT
      LAYER M4 ;
      RECT 130.872 19.776 130.896 19.800 ;
    END
  END rr_addr[8]
  PIN rr_addr[9]
    DIRECTION INPUT ;
    USE SIGNAL ;
    SHAPE ABUTMENT ;
    PORT
      LAYER M4 ;
      RECT 130.872 19.872 130.896 19.896 ;
    END
  END rr_addr[9]
  PIN rr_addr[10]
    DIRECTION INPUT ;
    USE SIGNAL ;
    SHAPE ABUTMENT ;
    PORT
      LAYER M4 ;
      RECT 130.872 19.968 130.896 19.992 ;
    END
  END rr_addr[10]
  PIN rr_addr[11]
    DIRECTION INPUT ;
    USE SIGNAL ;
    SHAPE ABUTMENT ;
    PORT
      LAYER M4 ;
      RECT 130.872 20.064 130.896 20.088 ;
    END
  END rr_addr[11]
  PIN rr_addr[12]
    DIRECTION INPUT ;
    USE SIGNAL ;
    SHAPE ABUTMENT ;
    PORT
      LAYER M4 ;
      RECT 130.872 20.160 130.896 20.184 ;
    END
  END rr_addr[12]
  PIN rr_addr[13]
    DIRECTION INPUT ;
    USE SIGNAL ;
    SHAPE ABUTMENT ;
    PORT
      LAYER M4 ;
      RECT 130.872 20.256 130.896 20.280 ;
    END
  END rr_addr[13]
  PIN cr_en[0]
    DIRECTION INPUT ;
    USE SIGNAL ;
    SHAPE ABUTMENT ;
    PORT
      LAYER M4 ;
      RECT 130.872 20.352 130.896 20.376 ;
    END
  END cr_en[0]
  PIN cr_en[1]
    DIRECTION INPUT ;
    USE SIGNAL ;
    SHAPE ABUTMENT ;
    PORT
      LAYER M4 ;
      RECT 130.872 20.448 130.896 20.472 ;
    END
  END cr_en[1]
  PIN cr_sel[0]
    DIRECTION INPUT ;
    USE SIGNAL ;
    SHAPE ABUTMENT ;
    PORT
      LAYER M4 ;
      RECT 130.872 20.544 130.896 20.568 ;
    END
  END cr_sel[0]
  PIN cr_sel[1]
    DIRECTION INPUT ;
    USE SIGNAL ;
    SHAPE ABUTMENT ;
    PORT
      LAYER M4 ;
      RECT 130.872 20.640 130.896 20.664 ;
    END
  END cr_sel[1]
  PIN cr_sel[2]
    DIRECTION INPUT ;
    USE SIGNAL ;
    SHAPE ABUTMENT ;
    PORT
      LAYER M4 ;
      RECT 130.872 20.736 130.896 20.760 ;
    END
  END cr_sel[2]
  PIN cr_sel[3]
    DIRECTION INPUT ;
    USE SIGNAL ;
    SHAPE ABUTMENT ;
    PORT
      LAYER M4 ;
      RECT 130.872 20.832 130.896 20.856 ;
    END
  END cr_sel[3]
  PIN cr_sel[4]
    DIRECTION INPUT ;
    USE SIGNAL ;
    SHAPE ABUTMENT ;
    PORT
      LAYER M4 ;
      RECT 130.872 20.928 130.896 20.952 ;
    END
  END cr_sel[4]
  PIN cr_sel[5]
    DIRECTION INPUT ;
    USE SIGNAL ;
    SHAPE ABUTMENT ;
    PORT
      LAYER M4 ;
      RECT 130.872 21.024 130.896 21.048 ;
    END
  END cr_sel[5]
  PIN cr_sel[6]
    DIRECTION INPUT ;
    USE SIGNAL ;
    SHAPE ABUTMENT ;
    PORT
      LAYER M4 ;
      RECT 130.872 21.120 130.896 21.144 ;
    END
  END cr_sel[6]
  PIN cr_sel[7]
    DIRECTION INPUT ;
    USE SIGNAL ;
    SHAPE ABUTMENT ;
    PORT
      LAYER M4 ;
      RECT 130.872 21.216 130.896 21.240 ;
    END
  END cr_sel[7]
  PIN cr_sel[8]
    DIRECTION INPUT ;
    USE SIGNAL ;
    SHAPE ABUTMENT ;
    PORT
      LAYER M4 ;
      RECT 130.872 21.312 130.896 21.336 ;
    END
  END cr_sel[8]
  PIN cr_sel[9]
    DIRECTION INPUT ;
    USE SIGNAL ;
    SHAPE ABUTMENT ;
    PORT
      LAYER M4 ;
      RECT 130.872 21.408 130.896 21.432 ;
    END
  END cr_sel[9]
  PIN cr_sel[10]
    DIRECTION INPUT ;
    USE SIGNAL ;
    SHAPE ABUTMENT ;
    PORT
      LAYER M4 ;
      RECT 130.872 21.504 130.896 21.528 ;
    END
  END cr_sel[10]
  PIN cr_sel[11]
    DIRECTION INPUT ;
    USE SIGNAL ;
    SHAPE ABUTMENT ;
    PORT
      LAYER M4 ;
      RECT 130.872 21.600 130.896 21.624 ;
    END
  END cr_sel[11]
  PIN VDD
    DIRECTION INOUT ;
    USE POWER ;
    PORT
      LAYER M4 ;
      RECT 0.300 0.384 130.596 0.480 ;
      RECT 0.300 1.152 130.596 1.248 ;
      RECT 0.300 1.920 130.596 2.016 ;
      RECT 0.300 2.688 130.596 2.784 ;
      RECT 0.300 3.456 130.596 3.552 ;
      RECT 0.300 4.224 130.596 4.320 ;
      RECT 0.300 4.992 130.596 5.088 ;
      RECT 0.300 5.760 130.596 5.856 ;
      RECT 0.300 6.528 130.596 6.624 ;
      RECT 0.300 7.296 130.596 7.392 ;
      RECT 0.300 8.064 130.596 8.160 ;
      RECT 0.300 8.832 130.596 8.928 ;
      RECT 0.300 9.600 130.596 9.696 ;
      RECT 0.300 10.368 130.596 10.464 ;
      RECT 0.300 11.136 130.596 11.232 ;
      RECT 0.300 11.904 130.596 12.000 ;
      RECT 0.300 12.672 130.596 12.768 ;
      RECT 0.300 13.440 130.596 13.536 ;
      RECT 0.300 14.208 130.596 14.304 ;
      RECT 0.300 14.976 130.596 15.072 ;
      RECT 0.300 15.744 130.596 15.840 ;
      RECT 0.300 16.512 130.596 16.608 ;
      RECT 0.300 17.280 130.596 17.376 ;
      RECT 0.300 18.048 130.596 18.144 ;
      RECT 0.300 18.816 130.596 18.912 ;
      RECT 0.300 19.584 130.596 19.680 ;
      RECT 0.300 20.352 130.596 20.448 ;
      RECT 0.300 21.120 130.596 21.216 ;
      RECT 0.300 21.888 130.596 21.984 ;
      RECT 0.300 22.656 130.596 22.752 ;
      RECT 0.300 23.424 130.596 23.520 ;
      RECT 0.300 24.192 130.596 24.288 ;
      RECT 0.300 24.960 130.596 25.056 ;
      RECT 0.300 25.728 130.596 25.824 ;
      RECT 0.300 26.496 130.596 26.592 ;
      RECT 0.300 27.264 130.596 27.360 ;
      RECT 0.300 28.032 130.596 28.128 ;
      RECT 0.300 28.800 130.596 28.896 ;
      RECT 0.300 29.568 130.596 29.664 ;
      RECT 0.300 30.336 130.596 30.432 ;
      RECT 0.300 31.104 130.596 31.200 ;
      RECT 0.300 31.872 130.596 31.968 ;
      RECT 0.300 32.640 130.596 32.736 ;
      RECT 0.300 33.408 130.596 33.504 ;
      RECT 0.300 34.176 130.596 34.272 ;
    END
  END VDD
  PIN VSS
    DIRECTION INOUT ;
    USE GROUND ;
    PORT
      LAYER M4 ;
      RECT 0.300 0.768 130.596 0.864 ;
      RECT 0.300 1.536 130.596 1.632 ;
      RECT 0.300 2.304 130.596 2.400 ;
      RECT 0.300 3.072 130.596 3.168 ;
      RECT 0.300 3.840 130.596 3.936 ;
      RECT 0.300 4.608 130.596 4.704 ;
      RECT 0.300 5.376 130.596 5.472 ;
      RECT 0.300 6.144 130.596 6.240 ;
      RECT 0.300 6.912 130.596 7.008 ;
      RECT 0.300 7.680 130.596 7.776 ;
      RECT 0.300 8.448 130.596 8.544 ;
      RECT 0.300 9.216 130.596 9.312 ;
      RECT 0.300 9.984 130.596 10.080 ;
      RECT 0.300 10.752 130.596 10.848 ;
      RECT 0.300 11.520 130.596 11.616 ;
      RECT 0.300 12.288 130.596 12.384 ;
      RECT 0.300 13.056 130.596 13.152 ;
      RECT 0.300 13.824 130.596 13.920 ;
      RECT 0.300 14.592 130.596 14.688 ;
      RECT 0.300 15.360 130.596 15.456 ;
      RECT 0.300 16.128 130.596 16.224 ;
      RECT 0.300 16.896 130.596 16.992 ;
      RECT 0.300 17.664 130.596 17.760 ;
      RECT 0.300 18.432 130.596 18.528 ;
      RECT 0.300 19.200 130.596 19.296 ;
      RECT 0.300 19.968 130.596 20.064 ;
      RECT 0.300 20.736 130.596 20.832 ;
      RECT 0.300 21.504 130.596 21.600 ;
      RECT 0.300 22.272 130.596 22.368 ;
      RECT 0.300 23.040 130.596 23.136 ;
      RECT 0.300 23.808 130.596 23.904 ;
      RECT 0.300 24.576 130.596 24.672 ;
      RECT 0.300 25.344 130.596 25.440 ;
      RECT 0.300 26.112 130.596 26.208 ;
      RECT 0.300 26.880 130.596 26.976 ;
      RECT 0.300 27.648 130.596 27.744 ;
      RECT 0.300 28.416 130.596 28.512 ;
      RECT 0.300 29.184 130.596 29.280 ;
      RECT 0.300 29.952 130.596 30.048 ;
      RECT 0.300 30.720 130.596 30.816 ;
      RECT 0.300 31.488 130.596 31.584 ;
      RECT 0.300 32.256 130.596 32.352 ;
      RECT 0.300 33.024 130.596 33.120 ;
      RECT 0.300 33.792 130.596 33.888 ;
      RECT 0.300 34.560 130.596 34.656 ;
    END
  END VSS
  OBS
    LAYER M1 ;
    RECT 0 0 130.896 34.830 ;
    LAYER M2 ;
    RECT 0 0 130.896 34.830 ;
    LAYER M3 ;
    RECT 0 0 130.896 34.830 ;
    LAYER M4 ;
    RECT 0.072 0 130.824 34.830 ;
  END
END ot_sram_2rw_512x64_m4_r2c2

END LIBRARY
